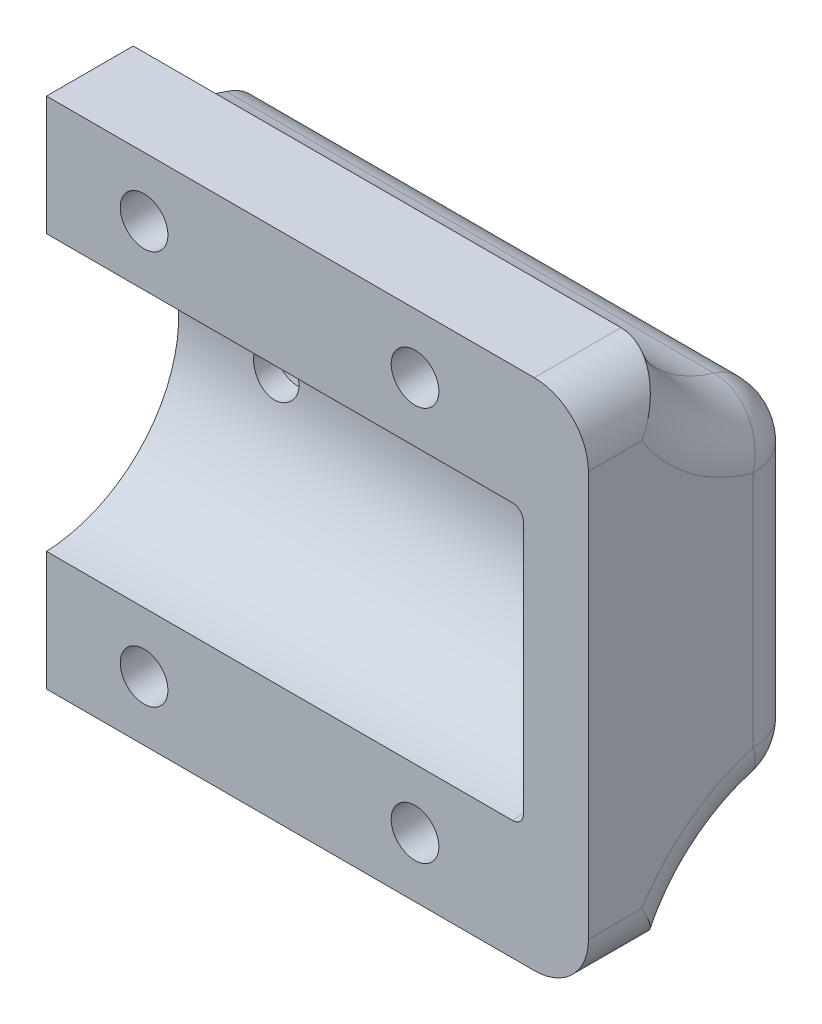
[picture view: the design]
ISO-10303-21;
HEADER;
FILE_DESCRIPTION(('STEP AP214'),'2;1');
FILE_NAME('part.step','',(''),(''),'','','');
FILE_SCHEMA(('AUTOMOTIVE_DESIGN { 1 0 10303 214 1 1 1 1 }'));
ENDSEC;
DATA;
#1=APPLICATION_CONTEXT('core data for automotive mechanical design processes');
#2=APPLICATION_PROTOCOL_DEFINITION('international standard','automotive_design',2000,#1);
#3=PRODUCT_CONTEXT('',#1,'mechanical');
#4=PRODUCT('Part','Part','',(#3));
#5=PRODUCT_RELATED_PRODUCT_CATEGORY('part','',(#4));
#6=PRODUCT_DEFINITION_FORMATION('','',#4);
#7=PRODUCT_DEFINITION_CONTEXT('part definition',#1,'design');
#8=PRODUCT_DEFINITION('design','',#6,#7);
#9=PRODUCT_DEFINITION_SHAPE('','',#8);
#10=(LENGTH_UNIT() NAMED_UNIT(*) SI_UNIT(.MILLI.,.METRE.));
#11=(NAMED_UNIT(*) PLANE_ANGLE_UNIT() SI_UNIT($,.RADIAN.));
#12=(NAMED_UNIT(*) SI_UNIT($,.STERADIAN.) SOLID_ANGLE_UNIT());
#13=UNCERTAINTY_MEASURE_WITH_UNIT(LENGTH_MEASURE(1.E-05),#10,'distance_accuracy_value','');
#14=(GEOMETRIC_REPRESENTATION_CONTEXT(3) GLOBAL_UNCERTAINTY_ASSIGNED_CONTEXT((#13)) GLOBAL_UNIT_ASSIGNED_CONTEXT((#10,
#11,#12)) REPRESENTATION_CONTEXT('',''));
#15=CARTESIAN_POINT('',(0.,0.,0.));
#16=DIRECTION('',(0.,0.,1.));
#17=DIRECTION('',(1.,0.,0.));
#18=AXIS2_PLACEMENT_3D('',#15,#16,#17);
#19=CARTESIAN_POINT('',(9.,18.1901536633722,-20.2));
#20=DIRECTION('',(0.,0.,1.));
#21=DIRECTION('',(1.,0.,0.));
#22=AXIS2_PLACEMENT_3D('',#19,#20,#21);
#23=CYLINDRICAL_SURFACE('',#22,2.1);
#24=CARTESIAN_POINT('',(11.1,18.1901536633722,-11.9525931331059));
#25=CARTESIAN_POINT('',(11.1000004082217,18.2649816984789,-11.8609818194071));
#26=CARTESIAN_POINT('',(11.0960052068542,18.3410787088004,-11.7703655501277));
#27=CARTESIAN_POINT('',(11.079154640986,18.4953429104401,-11.5916495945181));
#28=CARTESIAN_POINT('',(11.0662941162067,18.5735112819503,-11.5035514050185));
#29=CARTESIAN_POINT('',(11.0307187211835,18.7311800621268,-11.3305862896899));
#30=CARTESIAN_POINT('',(11.008006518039,18.8106801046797,-11.2457184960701));
#31=CARTESIAN_POINT('',(10.9516676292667,18.9699774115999,-11.0800757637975));
#32=CARTESIAN_POINT('',(10.9180497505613,19.0497743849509,-10.9992975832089));
#33=CARTESIAN_POINT('',(10.8308817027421,19.2241599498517,-10.8271837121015));
#34=CARTESIAN_POINT('',(10.7746996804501,19.3185407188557,-10.7369349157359));
#35=CARTESIAN_POINT('',(10.6433310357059,19.5024767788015,-10.5659415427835));
#36=CARTESIAN_POINT('',(10.5681775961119,19.5920401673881,-10.4851807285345));
#37=CARTESIAN_POINT('',(10.4124724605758,19.7473465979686,-10.3485749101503));
#38=CARTESIAN_POINT('',(10.3350536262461,19.8145413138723,-10.2908319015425));
#39=CARTESIAN_POINT('',(10.1666705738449,19.9393955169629,-10.185421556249));
#40=CARTESIAN_POINT('',(10.0757076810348,19.9970559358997,-10.1377532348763));
#41=CARTESIAN_POINT('',(9.88077297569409,20.0997260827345,-10.0540279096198));
#42=CARTESIAN_POINT('',(9.77669657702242,20.1446234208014,-10.0180736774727));
#43=CARTESIAN_POINT('',(9.55915324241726,20.217581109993,-9.96014901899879));
#44=CARTESIAN_POINT('',(9.44569603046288,20.2456586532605,-9.93816431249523));
#45=CARTESIAN_POINT('',(9.23105328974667,20.2798029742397,-9.91150655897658));
#46=CARTESIAN_POINT('',(9.13053901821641,20.2885138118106,-9.90475177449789));
#47=CARTESIAN_POINT('',(8.92919774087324,20.291368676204,-9.90253351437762));
#48=CARTESIAN_POINT('',(8.8283709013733,20.2855194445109,-9.90706481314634));
#49=CARTESIAN_POINT('',(8.63670917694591,20.2605900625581,-9.9264973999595));
#50=CARTESIAN_POINT('',(8.54566955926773,20.2424669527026,-9.94064885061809));
#51=CARTESIAN_POINT('',(8.36851717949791,20.1950573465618,-9.97800381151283));
#52=CARTESIAN_POINT('',(8.28240458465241,20.1657704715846,-10.0012076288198));
#53=CARTESIAN_POINT('',(8.11351382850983,20.0961520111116,-10.057031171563));
#54=CARTESIAN_POINT('',(8.03102032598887,20.0554141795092,-10.0900002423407));
#55=CARTESIAN_POINT('',(7.87469363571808,19.9654928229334,-10.1638885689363));
#56=CARTESIAN_POINT('',(7.80086354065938,19.916306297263,-10.2048106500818));
#57=CARTESIAN_POINT('',(7.65342350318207,19.8045812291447,-10.2993903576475));
#58=CARTESIAN_POINT('',(7.58112519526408,19.7411373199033,-10.3540156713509));
#59=CARTESIAN_POINT('',(7.44864950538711,19.6086416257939,-10.4705997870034));
#60=CARTESIAN_POINT('',(7.38848087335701,19.539585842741,-10.5325638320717));
#61=CARTESIAN_POINT('',(7.24928027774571,19.3582334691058,-10.6991263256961));
#62=CARTESIAN_POINT('',(7.1786764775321,19.2434643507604,-10.8081002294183));
#63=CARTESIAN_POINT('',(7.06304899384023,19.0117757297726,-11.0368323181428));
#64=CARTESIAN_POINT('',(7.01808035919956,18.8948521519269,-11.1566130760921));
#65=CARTESIAN_POINT('',(6.96003177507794,18.6960820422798,-11.3684940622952));
#66=CARTESIAN_POINT('',(6.94151292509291,18.6137519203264,-11.458733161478));
#67=CARTESIAN_POINT('',(6.9146193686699,18.4509240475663,-11.6423762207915));
#68=CARTESIAN_POINT('',(6.90624901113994,18.3704270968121,-11.7357815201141));
#69=CARTESIAN_POINT('',(6.89860747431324,18.211798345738,-11.9252394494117));
#70=CARTESIAN_POINT('',(6.89935534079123,18.1336718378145,-12.02129720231));
#71=CARTESIAN_POINT('',(6.90909288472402,17.9803767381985,-12.215348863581));
#72=CARTESIAN_POINT('',(6.91808479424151,17.9052089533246,-12.3133432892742));
#73=CARTESIAN_POINT('',(6.94847966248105,17.7297495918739,-12.548910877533));
#74=CARTESIAN_POINT('',(6.97333321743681,17.6309580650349,-12.6871627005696));
#75=CARTESIAN_POINT('',(7.03594105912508,17.4401097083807,-12.9654428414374));
#76=CARTESIAN_POINT('',(7.07370249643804,17.3480566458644,-13.1054721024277));
#77=CARTESIAN_POINT('',(7.16111607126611,17.1712270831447,-13.3858891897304));
#78=CARTESIAN_POINT('',(7.21073913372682,17.0864334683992,-13.5262753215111));
#79=CARTESIAN_POINT('',(7.32164906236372,16.9241337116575,-13.8065398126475));
#80=CARTESIAN_POINT('',(7.38292820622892,16.8466227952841,-13.9464184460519));
#81=CARTESIAN_POINT('',(7.50653107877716,16.7114833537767,-14.2008953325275));
#82=CARTESIAN_POINT('',(7.56695979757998,16.6526994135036,-14.3158028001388));
#83=CARTESIAN_POINT('',(7.69768262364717,16.5404745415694,-14.5431696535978));
#84=CARTESIAN_POINT('',(7.76800164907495,16.4870477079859,-14.6556220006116));
#85=CARTESIAN_POINT('',(7.88295871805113,16.4112939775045,-14.8208015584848));
#86=CARTESIAN_POINT('',(7.92311995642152,16.386643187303,-14.8755872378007));
#87=CARTESIAN_POINT('',(8.00703452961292,16.3391136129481,-14.9831227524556));
#88=CARTESIAN_POINT('',(8.0507860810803,16.316233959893,-15.0358735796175));
#89=CARTESIAN_POINT('',(8.14233999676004,16.2726083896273,-15.1382052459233));
#90=CARTESIAN_POINT('',(8.19012175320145,16.2518526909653,-15.1878001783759));
#91=CARTESIAN_POINT('',(8.29073639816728,16.2128182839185,-15.282583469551));
#92=CARTESIAN_POINT('',(8.34355978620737,16.1945350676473,-15.327779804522));
#93=CARTESIAN_POINT('',(8.44011950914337,16.1657201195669,-15.4000154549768));
#94=CARTESIAN_POINT('',(8.48242076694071,16.154432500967,-15.4286501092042));
#95=CARTESIAN_POINT('',(8.57060452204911,16.1340245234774,-15.4808751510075));
#96=CARTESIAN_POINT('',(8.61648761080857,16.1249045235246,-15.5044647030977));
#97=CARTESIAN_POINT('',(8.71244367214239,16.1093604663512,-15.5449251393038));
#98=CARTESIAN_POINT('',(8.76256654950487,16.1029761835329,-15.5616967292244));
#99=CARTESIAN_POINT('',(8.86533402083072,16.09384669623,-15.5857480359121));
#100=CARTESIAN_POINT('',(8.9179716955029,16.0910920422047,-15.5930523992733));
#101=CARTESIAN_POINT('',(9.01742427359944,16.0897076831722,-15.5967198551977));
#102=CARTESIAN_POINT('',(9.06419041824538,16.0906280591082,-15.5942763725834));
#103=CARTESIAN_POINT('',(9.15647273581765,16.0954799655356,-15.5814486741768));
#104=CARTESIAN_POINT('',(9.2019873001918,16.099415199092,-15.5710546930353));
#105=CARTESIAN_POINT('',(9.30132155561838,16.1111440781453,-15.5402783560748));
#106=CARTESIAN_POINT('',(9.35448350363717,16.1196412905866,-15.5180867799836));
#107=CARTESIAN_POINT('',(9.45643323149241,16.1396935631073,-15.466303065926));
#108=CARTESIAN_POINT('',(9.50521035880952,16.1512558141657,-15.4366935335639));
#109=CARTESIAN_POINT('',(9.59370830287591,16.1753614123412,-15.3757510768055));
#110=CARTESIAN_POINT('',(9.63384350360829,16.1876779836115,-15.3449169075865));
#111=CARTESIAN_POINT('',(9.71115189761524,16.2138120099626,-15.2802852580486));
#112=CARTESIAN_POINT('',(9.74832251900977,16.2276307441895,-15.2464852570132));
#113=CARTESIAN_POINT('',(9.85609061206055,16.2710027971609,-15.1417608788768));
#114=CARTESIAN_POINT('',(9.92279602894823,16.3024287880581,-15.0676226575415));
#115=CARTESIAN_POINT('',(10.0559206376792,16.3731851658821,-14.9052652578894));
#116=CARTESIAN_POINT('',(10.1212987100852,16.4130123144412,-14.8164349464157));
#117=CARTESIAN_POINT('',(10.2442408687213,16.4968163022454,-14.6352855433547));
#118=CARTESIAN_POINT('',(10.3017961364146,16.540797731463,-14.5429626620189));
#119=CARTESIAN_POINT('',(10.4103940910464,16.6326381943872,-14.3560848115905));
#120=CARTESIAN_POINT('',(10.4614192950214,16.6805070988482,-14.2615246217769));
#121=CARTESIAN_POINT('',(10.5574926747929,16.7798395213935,-14.0712530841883));
#122=CARTESIAN_POINT('',(10.6025395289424,16.8313038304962,-13.9755414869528));
#123=CARTESIAN_POINT('',(10.7074136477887,16.9634097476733,-13.7372076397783));
#124=CARTESIAN_POINT('',(10.7638752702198,17.0461410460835,-13.5942491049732));
#125=CARTESIAN_POINT('',(10.8646655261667,17.2190559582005,-13.3084330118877));
#126=CARTESIAN_POINT('',(10.9089860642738,17.3092444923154,-13.1655755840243));
#127=CARTESIAN_POINT('',(10.9846343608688,17.4963501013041,-12.8818015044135));
#128=CARTESIAN_POINT('',(11.0160208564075,17.5932343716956,-12.7408789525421));
#129=CARTESIAN_POINT('',(11.0648004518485,17.793645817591,-12.4614810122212));
#130=CARTESIAN_POINT('',(11.0822089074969,17.8971655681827,-12.3230031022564));
#131=CARTESIAN_POINT('',(11.0944283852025,18.0342349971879,-12.1471010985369));
#132=CARTESIAN_POINT('',(11.0965021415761,18.0650709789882,-12.1079938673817));
#133=CARTESIAN_POINT('',(11.0992886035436,18.1272469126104,-12.0300628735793));
#134=CARTESIAN_POINT('',(11.0999998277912,18.1585873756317,-11.9912394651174));
#135=CARTESIAN_POINT('',(11.1,18.1901536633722,-11.9525931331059));
#136=B_SPLINE_CURVE_WITH_KNOTS('',3,(#24,#25,#26,#27,#28,#29,#30,#31,#32,#33,#34,#35,#36,#37,
#38,#39,#40,#41,#42,#43,#44,#45,#46,#47,#48,#49,#50,#51,#52,#53,#54,#55,#56,#57,#58,#59,#60,#61,
#62,#63,#64,#65,#66,#67,#68,#69,#70,#71,#72,#73,#74,#75,#76,#77,#78,#79,#80,#81,#82,#83,#84,#85,
#86,#87,#88,#89,#90,#91,#92,#93,#94,#95,#96,#97,#98,#99,#100,#101,#102,#103,#104,#105,#106,#107,
#108,#109,#110,#111,#112,#113,#114,#115,#116,#117,#118,#119,#120,#121,#122,#123,#124,#125,#126,
#127,#128,#129,#130,#131,#132,#133,#134,#135),.UNSPECIFIED.,.T.,.F.,(4,2,2,2,2,2,2,2,2,2,2,2,2,
2,2,2,2,2,2,2,2,2,2,2,2,2,2,2,2,2,2,2,2,2,2,2,2,2,2,2,2,2,2,2,2,2,2,2,2,2,2,2,2,2,2,4),(0.,
0.354821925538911,0.709850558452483,1.06478313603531,1.41942979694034,1.84446916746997,
2.26877019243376,2.62034948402,2.97189439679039,3.32644530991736,3.6806332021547,
3.98236309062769,4.2839533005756,4.56438465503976,4.84482552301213,5.13685035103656,
5.42897911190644,5.75961189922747,6.09048234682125,6.60747457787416,7.12557285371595,
7.49574693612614,7.86607959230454,8.23718591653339,8.60839274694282,9.12286436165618,
9.63762144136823,10.15112946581,10.6642984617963,11.0914931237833,11.5197840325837,
11.7364714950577,11.9530519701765,12.168585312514,12.3837202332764,12.5403530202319,
12.6970117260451,12.8558765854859,13.014327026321,13.1540104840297,13.2938657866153,
13.4675871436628,13.6417197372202,13.7977587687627,13.9539317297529,14.2668418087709,
14.618178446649,14.9699079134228,15.3225601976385,15.675290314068,16.1983356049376,
16.7217288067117,17.2427182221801,17.7631345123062,17.9126540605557,18.062336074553),.UNSPECIFIED.);
#137=CARTESIAN_POINT('',(11.1,18.1901536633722,-11.9525931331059));
#138=VERTEX_POINT('',#137);
#139=EDGE_CURVE('E307',#138,#138,#136,.T.);
#140=ORIENTED_EDGE('',*,*,#139,.F.);
#141=EDGE_LOOP('',(#140));
#142=FACE_BOUND('',#141,.T.);
#143=CARTESIAN_POINT('',(9.,18.1901536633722,-5.));
#144=DIRECTION('',(0.,0.,1.));
#145=DIRECTION('',(1.,0.,0.));
#146=AXIS2_PLACEMENT_3D('',#143,#144,#145);
#147=CIRCLE('',#146,2.1);
#148=CARTESIAN_POINT('',(11.1,18.1901536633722,-5.));
#149=VERTEX_POINT('',#148);
#150=EDGE_CURVE('E445',#149,#149,#147,.F.);
#151=ORIENTED_EDGE('',*,*,#150,.F.);
#152=EDGE_LOOP('',(#151));
#153=FACE_BOUND('',#152,.T.);
#154=ADVANCED_FACE('F44',(#142,#153),#23,.F.);
#155=CARTESIAN_POINT('',(34.,-18.1901536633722,-20.2));
#156=DIRECTION('',(0.,0.,1.));
#157=DIRECTION('',(1.,0.,0.));
#158=AXIS2_PLACEMENT_3D('',#155,#156,#157);
#159=CYLINDRICAL_SURFACE('',#158,2.1);
#160=CARTESIAN_POINT('',(36.1,-18.1901536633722,-11.9525931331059));
#161=CARTESIAN_POINT('',(36.100002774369,-18.0940217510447,-12.0702912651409));
#162=CARTESIAN_POINT('',(36.0934104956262,-17.9999131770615,-12.1897181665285));
#163=CARTESIAN_POINT('',(36.0685563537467,-17.8164509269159,-12.4310664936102));
#164=CARTESIAN_POINT('',(36.0502835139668,-17.7271018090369,-12.5529901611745));
#165=CARTESIAN_POINT('',(36.0030754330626,-17.5530775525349,-12.799241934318));
#166=CARTESIAN_POINT('',(35.9740755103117,-17.4684344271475,-12.9235801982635));
#167=CARTESIAN_POINT('',(35.9062633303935,-17.3047106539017,-13.1731361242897));
#168=CARTESIAN_POINT('',(35.8674552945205,-17.2256276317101,-13.2983533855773));
#169=CARTESIAN_POINT('',(35.7780373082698,-17.0689165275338,-13.5559370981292));
#170=CARTESIAN_POINT('',(35.7268925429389,-16.9916118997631,-13.6883152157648));
#171=CARTESIAN_POINT('',(35.614024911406,-16.8434507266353,-13.9523654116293));
#172=CARTESIAN_POINT('',(35.5522914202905,-16.7726007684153,-14.084036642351));
#173=CARTESIAN_POINT('',(35.4177380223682,-16.6380390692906,-14.3444353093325));
#174=CARTESIAN_POINT('',(35.3449763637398,-16.574292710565,-14.4731743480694));
#175=CARTESIAN_POINT('',(35.2257392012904,-16.4842757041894,-14.6623940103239));
#176=CARTESIAN_POINT('',(35.184346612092,-16.4552239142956,-14.7247727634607));
#177=CARTESIAN_POINT('',(35.0976680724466,-16.399121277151,-14.8476833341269));
#178=CARTESIAN_POINT('',(35.0523841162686,-16.3720694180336,-14.9082160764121));
#179=CARTESIAN_POINT('',(34.9748896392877,-16.3298454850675,-15.0045736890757));
#180=CARTESIAN_POINT('',(34.9440728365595,-16.3139938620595,-15.0412225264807));
#181=CARTESIAN_POINT('',(34.8803646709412,-16.283268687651,-15.1131282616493));
#182=CARTESIAN_POINT('',(34.847472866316,-16.2683953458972,-15.1483848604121));
#183=CARTESIAN_POINT('',(34.7794212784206,-16.2398046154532,-15.2169564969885));
#184=CARTESIAN_POINT('',(34.7442675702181,-16.2260843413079,-15.2502763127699));
#185=CARTESIAN_POINT('',(34.6713037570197,-16.199964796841,-15.3144084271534));
#186=CARTESIAN_POINT('',(34.6334954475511,-16.1875646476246,-15.3452223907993));
#187=CARTESIAN_POINT('',(34.5509635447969,-16.1632174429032,-15.4063298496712));
#188=CARTESIAN_POINT('',(34.5059256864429,-16.151435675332,-15.4362723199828));
#189=CARTESIAN_POINT('',(34.4118604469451,-16.1303757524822,-15.4902768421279));
#190=CARTESIAN_POINT('',(34.3628373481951,-16.1210949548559,-15.5143450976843));
#191=CARTESIAN_POINT('',(34.2702128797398,-16.1071844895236,-15.5506399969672));
#192=CARTESIAN_POINT('',(34.2272345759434,-16.1020171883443,-15.5642210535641));
#193=CARTESIAN_POINT('',(34.1394620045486,-16.0943286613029,-15.5844806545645));
#194=CARTESIAN_POINT('',(34.0946705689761,-16.0918034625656,-15.59116956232));
#195=CARTESIAN_POINT('',(34.0043045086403,-16.0896702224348,-15.5968178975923));
#196=CARTESIAN_POINT('',(33.9587272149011,-16.090075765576,-15.5957413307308));
#197=CARTESIAN_POINT('',(33.868520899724,-16.0937858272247,-15.5859254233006));
#198=CARTESIAN_POINT('',(33.8238928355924,-16.097093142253,-15.5771786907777));
#199=CARTESIAN_POINT('',(33.726945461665,-16.1072888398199,-15.5503739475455));
#200=CARTESIAN_POINT('',(33.6751610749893,-16.1148165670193,-15.5306610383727));
#201=CARTESIAN_POINT('',(33.5755980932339,-16.1328598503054,-15.4838919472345));
#202=CARTESIAN_POINT('',(33.5278292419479,-16.1433824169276,-15.4568185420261));
#203=CARTESIAN_POINT('',(33.4024008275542,-16.1752954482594,-15.3757041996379));
#204=CARTESIAN_POINT('',(33.3287147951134,-16.1989735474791,-15.3165116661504));
#205=CARTESIAN_POINT('',(33.1907907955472,-16.2509220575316,-15.189824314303));
#206=CARTESIAN_POINT('',(33.1265834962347,-16.2792067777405,-15.1223037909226));
#207=CARTESIAN_POINT('',(32.9987070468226,-16.342707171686,-14.974543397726));
#208=CARTESIAN_POINT('',(32.9359212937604,-16.3783449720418,-14.8937288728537));
#209=CARTESIAN_POINT('',(32.8175149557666,-16.4533074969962,-14.7285800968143));
#210=CARTESIAN_POINT('',(32.7619024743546,-16.4926363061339,-14.6442420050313));
#211=CARTESIAN_POINT('',(32.6565918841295,-16.5746922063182,-14.4732710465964));
#212=CARTESIAN_POINT('',(32.606907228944,-16.6174266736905,-14.3866334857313));
#213=CARTESIAN_POINT('',(32.5128745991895,-16.7060287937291,-14.212063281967));
#214=CARTESIAN_POINT('',(32.468528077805,-16.7518972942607,-14.1241302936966));
#215=CARTESIAN_POINT('',(32.3587641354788,-16.8760511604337,-13.8927485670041));
#216=CARTESIAN_POINT('',(32.297343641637,-16.9567929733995,-13.748703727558));
#217=CARTESIAN_POINT('',(32.1868139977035,-17.1259390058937,-13.4602836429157));
#218=CARTESIAN_POINT('',(32.1377128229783,-17.214348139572,-13.3159082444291));
#219=CARTESIAN_POINT('',(32.0523311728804,-17.3984085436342,-13.0283206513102));
#220=CARTESIAN_POINT('',(32.0160297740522,-17.4940476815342,-12.8851069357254));
#221=CARTESIAN_POINT('',(31.9572461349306,-17.6923194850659,-12.600768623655));
#222=CARTESIAN_POINT('',(31.9347547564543,-17.7949474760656,-12.4596427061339));
#223=CARTESIAN_POINT('',(31.9104341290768,-17.9697843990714,-12.2291816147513));
#224=CARTESIAN_POINT('',(31.9041388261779,-18.0401551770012,-12.138908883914));
#225=CARTESIAN_POINT('',(31.8987878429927,-18.1833865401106,-11.960089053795));
#226=CARTESIAN_POINT('',(31.8997334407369,-18.256247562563,-11.8715422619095));
#227=CARTESIAN_POINT('',(31.9096034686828,-18.4039577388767,-11.6967795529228));
#228=CARTESIAN_POINT('',(31.918515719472,-18.4788036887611,-11.6105602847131));
#229=CARTESIAN_POINT('',(31.945151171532,-18.630028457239,-11.4408760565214));
#230=CARTESIAN_POINT('',(31.9628737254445,-18.7064071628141,-11.3574108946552));
#231=CARTESIAN_POINT('',(32.0185967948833,-18.8957075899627,-11.1558189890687));
#232=CARTESIAN_POINT('',(32.0621933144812,-19.0091176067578,-11.0396084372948));
#233=CARTESIAN_POINT('',(32.1735260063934,-19.2340346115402,-10.817266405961));
#234=CARTESIAN_POINT('',(32.2412305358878,-19.345543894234,-10.7111219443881));
#235=CARTESIAN_POINT('',(32.3843524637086,-19.5356281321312,-10.5359771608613));
#236=CARTESIAN_POINT('',(32.4541763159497,-19.6157637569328,-10.4641234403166));
#237=CARTESIAN_POINT('',(32.610166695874,-19.768194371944,-10.3304693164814));
#238=CARTESIAN_POINT('',(32.6963132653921,-19.8404987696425,-10.2686568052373));
#239=CARTESIAN_POINT('',(32.8685503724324,-19.9618675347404,-10.1668048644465));
#240=CARTESIAN_POINT('',(32.9521889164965,-20.0127943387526,-10.1248511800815));
#241=CARTESIAN_POINT('',(33.129289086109,-20.1037240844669,-10.0508526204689));
#242=CARTESIAN_POINT('',(33.2227474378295,-20.1437306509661,-10.0188044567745));
#243=CARTESIAN_POINT('',(33.4179258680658,-20.2105207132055,-9.96573471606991));
#244=CARTESIAN_POINT('',(33.5196901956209,-20.2372271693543,-9.94477733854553));
#245=CARTESIAN_POINT('',(33.7278054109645,-20.2751180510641,-9.91514433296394));
#246=CARTESIAN_POINT('',(33.8341541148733,-20.2863097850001,-9.90646292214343));
#247=CARTESIAN_POINT('',(34.0366479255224,-20.2920236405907,-9.90202559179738));
#248=CARTESIAN_POINT('',(34.1327262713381,-20.2881309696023,-9.90504055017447));
#249=CARTESIAN_POINT('',(34.3225911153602,-20.2674231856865,-9.92116439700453));
#250=CARTESIAN_POINT('',(34.4163780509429,-20.2506105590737,-9.93427134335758));
#251=CARTESIAN_POINT('',(34.5974377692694,-20.2055009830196,-9.96974995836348));
#252=CARTESIAN_POINT('',(34.6847967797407,-20.1774137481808,-9.99195258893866));
#253=CARTESIAN_POINT('',(34.852892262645,-20.1112835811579,-10.0448432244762));
#254=CARTESIAN_POINT('',(34.9336274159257,-20.073238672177,-10.0755329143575));
#255=CARTESIAN_POINT('',(35.0935007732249,-19.9854926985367,-10.1473346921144));
#256=CARTESIAN_POINT('',(35.1719581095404,-19.9350890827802,-10.1890976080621));
#257=CARTESIAN_POINT('',(35.3187149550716,-19.8270147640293,-10.2802635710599));
#258=CARTESIAN_POINT('',(35.3870091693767,-19.7693403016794,-10.3296705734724));
#259=CARTESIAN_POINT('',(35.5423015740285,-19.6210739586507,-10.4592301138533));
#260=CARTESIAN_POINT('',(35.6234437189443,-19.5275480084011,-10.5430681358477));
#261=CARTESIAN_POINT('',(35.7646603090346,-19.3348454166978,-10.7214260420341));
#262=CARTESIAN_POINT('',(35.8246818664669,-19.2356553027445,-10.8159719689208));
#263=CARTESIAN_POINT('',(35.9451724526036,-18.9967063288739,-11.0514988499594));
#264=CARTESIAN_POINT('',(35.996724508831,-18.8561825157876,-11.1962312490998));
#265=CARTESIAN_POINT('',(36.068685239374,-18.5788492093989,-11.4959765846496));
#266=CARTESIAN_POINT('',(36.089108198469,-18.4420380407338,-11.6509847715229));
#267=CARTESIAN_POINT('',(36.0988988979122,-18.2689700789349,-11.8567958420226));
#268=CARTESIAN_POINT('',(36.0999988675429,-18.2293933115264,-11.9045504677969));
#269=CARTESIAN_POINT('',(36.1,-18.1901536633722,-11.9525931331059));
#270=B_SPLINE_CURVE_WITH_KNOTS('',3,(#160,#161,#162,#163,#164,#165,#166,#167,#168,#169,#170,
#171,#172,#173,#174,#175,#176,#177,#178,#179,#180,#181,#182,#183,#184,#185,#186,#187,#188,#189,
#190,#191,#192,#193,#194,#195,#196,#197,#198,#199,#200,#201,#202,#203,#204,#205,#206,#207,#208,
#209,#210,#211,#212,#213,#214,#215,#216,#217,#218,#219,#220,#221,#222,#223,#224,#225,#226,#227,
#228,#229,#230,#231,#232,#233,#234,#235,#236,#237,#238,#239,#240,#241,#242,#243,#244,#245,#246,
#247,#248,#249,#250,#251,#252,#253,#254,#255,#256,#257,#258,#259,#260,#261,#262,#263,#264,#265,
#266,#267,#268,#269),.UNSPECIFIED.,.T.,.F.,(4,2,2,2,2,2,2,2,2,2,2,2,2,2,2,2,2,2,2,2,2,2,2,2,2,2,
2,2,2,2,2,2,2,2,2,2,2,2,2,2,2,2,2,2,2,2,2,2,2,2,2,2,2,2,4),(0.,0.455877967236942,
0.912184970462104,1.37128947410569,1.83019672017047,2.31453335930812,2.79935886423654,
3.28170754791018,3.52251308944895,3.76319594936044,3.9144562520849,4.06574886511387,
4.21665084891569,4.36745173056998,4.53312465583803,4.6986218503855,4.8341861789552,
4.96954636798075,5.10553437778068,5.24165358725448,5.40846713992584,5.57567443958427,
5.86634597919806,6.1579382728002,6.48253321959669,6.8074917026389,7.13317421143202,
7.45894518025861,7.98682932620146,8.51505434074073,9.04241183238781,9.56941999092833,
9.91308938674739,10.2568194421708,10.6000249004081,10.9432051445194,11.4458568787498,
11.9478512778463,12.3313441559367,12.7143711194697,13.0326529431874,13.3508289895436,
13.6708272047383,13.9906746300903,14.2778676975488,14.5650055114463,14.8470330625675,
15.1291166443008,15.4344648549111,15.7399715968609,16.1860724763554,16.6332826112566,
17.2545398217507,17.8755118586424,18.0615946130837),.UNSPECIFIED.);
#271=CARTESIAN_POINT('',(36.1,-18.1901536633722,-11.9525931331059));
#272=VERTEX_POINT('',#271);
#273=EDGE_CURVE('E362',#272,#272,#270,.T.);
#274=ORIENTED_EDGE('',*,*,#273,.F.);
#275=EDGE_LOOP('',(#274));
#276=FACE_BOUND('',#275,.T.);
#277=CARTESIAN_POINT('',(34.,-18.1901536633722,-5.));
#278=DIRECTION('',(0.,0.,1.));
#279=DIRECTION('',(1.,0.,0.));
#280=AXIS2_PLACEMENT_3D('',#277,#278,#279);
#281=CIRCLE('',#280,2.1);
#282=CARTESIAN_POINT('',(36.1,-18.1901536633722,-5.));
#283=VERTEX_POINT('',#282);
#284=EDGE_CURVE('E438',#283,#283,#281,.F.);
#285=ORIENTED_EDGE('',*,*,#284,.F.);
#286=EDGE_LOOP('',(#285));
#287=FACE_BOUND('',#286,.T.);
#288=ADVANCED_FACE('F336',(#276,#287),#159,.F.);
#289=CARTESIAN_POINT('',(9.,-18.1901536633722,-20.2));
#290=DIRECTION('',(0.,0.,1.));
#291=DIRECTION('',(1.,0.,0.));
#292=AXIS2_PLACEMENT_3D('',#289,#290,#291);
#293=CYLINDRICAL_SURFACE('',#292,2.1);
#294=CARTESIAN_POINT('',(11.1,-18.1901536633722,-11.9525931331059));
#295=CARTESIAN_POINT('',(11.100002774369,-18.0940217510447,-12.0702912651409));
#296=CARTESIAN_POINT('',(11.0934104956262,-17.9999131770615,-12.1897181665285));
#297=CARTESIAN_POINT('',(11.0685563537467,-17.8164509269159,-12.4310664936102));
#298=CARTESIAN_POINT('',(11.0502835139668,-17.7271018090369,-12.5529901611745));
#299=CARTESIAN_POINT('',(11.0030754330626,-17.5530775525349,-12.799241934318));
#300=CARTESIAN_POINT('',(10.9740755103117,-17.4684344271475,-12.9235801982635));
#301=CARTESIAN_POINT('',(10.9062633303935,-17.3047106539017,-13.1731361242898));
#302=CARTESIAN_POINT('',(10.8674552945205,-17.2256276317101,-13.2983533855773));
#303=CARTESIAN_POINT('',(10.7780373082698,-17.0689165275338,-13.5559370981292));
#304=CARTESIAN_POINT('',(10.7268925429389,-16.9916118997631,-13.6883152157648));
#305=CARTESIAN_POINT('',(10.614024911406,-16.8434507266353,-13.9523654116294));
#306=CARTESIAN_POINT('',(10.5522914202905,-16.7726007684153,-14.084036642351));
#307=CARTESIAN_POINT('',(10.4177380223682,-16.6380390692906,-14.3444353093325));
#308=CARTESIAN_POINT('',(10.3449763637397,-16.574292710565,-14.4731743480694));
#309=CARTESIAN_POINT('',(10.2257392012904,-16.4842757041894,-14.662394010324));
#310=CARTESIAN_POINT('',(10.184346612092,-16.4552239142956,-14.7247727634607));
#311=CARTESIAN_POINT('',(10.0976680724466,-16.399121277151,-14.847683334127));
#312=CARTESIAN_POINT('',(10.0523841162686,-16.3720694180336,-14.9082160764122));
#313=CARTESIAN_POINT('',(9.97488963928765,-16.3298454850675,-15.0045736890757));
#314=CARTESIAN_POINT('',(9.94407283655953,-16.3139938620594,-15.0412225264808));
#315=CARTESIAN_POINT('',(9.88036467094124,-16.283268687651,-15.1131282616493));
#316=CARTESIAN_POINT('',(9.84747286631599,-16.2683953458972,-15.1483848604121));
#317=CARTESIAN_POINT('',(9.77942127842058,-16.2398046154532,-15.2169564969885));
#318=CARTESIAN_POINT('',(9.74426757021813,-16.2260843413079,-15.2502763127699));
#319=CARTESIAN_POINT('',(9.67130375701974,-16.199964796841,-15.3144084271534));
#320=CARTESIAN_POINT('',(9.63349544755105,-16.1875646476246,-15.3452223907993));
#321=CARTESIAN_POINT('',(9.55096354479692,-16.1632174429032,-15.4063298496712));
#322=CARTESIAN_POINT('',(9.50592568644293,-16.151435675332,-15.4362723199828));
#323=CARTESIAN_POINT('',(9.41186044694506,-16.1303757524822,-15.4902768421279));
#324=CARTESIAN_POINT('',(9.36283734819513,-16.1210949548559,-15.5143450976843));
#325=CARTESIAN_POINT('',(9.27021287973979,-16.1071844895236,-15.5506399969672));
#326=CARTESIAN_POINT('',(9.22723457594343,-16.1020171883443,-15.5642210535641));
#327=CARTESIAN_POINT('',(9.1394620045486,-16.0943286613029,-15.5844806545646));
#328=CARTESIAN_POINT('',(9.09467056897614,-16.0918034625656,-15.59116956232));
#329=CARTESIAN_POINT('',(9.00430450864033,-16.0896702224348,-15.5968178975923));
#330=CARTESIAN_POINT('',(8.95872721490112,-16.090075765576,-15.5957413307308));
#331=CARTESIAN_POINT('',(8.86852089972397,-16.0937858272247,-15.5859254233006));
#332=CARTESIAN_POINT('',(8.8238928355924,-16.097093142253,-15.5771786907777));
#333=CARTESIAN_POINT('',(8.72694546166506,-16.1072888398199,-15.5503739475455));
#334=CARTESIAN_POINT('',(8.67516107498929,-16.1148165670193,-15.5306610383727));
#335=CARTESIAN_POINT('',(8.57559809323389,-16.1328598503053,-15.4838919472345));
#336=CARTESIAN_POINT('',(8.52782924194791,-16.1433824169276,-15.4568185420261));
#337=CARTESIAN_POINT('',(8.40240082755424,-16.1752954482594,-15.3757041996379));
#338=CARTESIAN_POINT('',(8.32871479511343,-16.1989735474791,-15.3165116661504));
#339=CARTESIAN_POINT('',(8.19079079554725,-16.2509220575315,-15.189824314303));
#340=CARTESIAN_POINT('',(8.12658349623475,-16.2792067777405,-15.1223037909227));
#341=CARTESIAN_POINT('',(7.99870704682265,-16.342707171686,-14.974543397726));
#342=CARTESIAN_POINT('',(7.93592129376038,-16.3783449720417,-14.8937288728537));
#343=CARTESIAN_POINT('',(7.81751495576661,-16.4533074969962,-14.7285800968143));
#344=CARTESIAN_POINT('',(7.76190247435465,-16.4926363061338,-14.6442420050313));
#345=CARTESIAN_POINT('',(7.65659188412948,-16.5746922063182,-14.4732710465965));
#346=CARTESIAN_POINT('',(7.60690722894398,-16.6174266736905,-14.3866334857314));
#347=CARTESIAN_POINT('',(7.51287459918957,-16.7060287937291,-14.212063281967));
#348=CARTESIAN_POINT('',(7.468528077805,-16.7518972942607,-14.1241302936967));
#349=CARTESIAN_POINT('',(7.3587641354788,-16.8760511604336,-13.8927485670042));
#350=CARTESIAN_POINT('',(7.29734364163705,-16.9567929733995,-13.748703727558));
#351=CARTESIAN_POINT('',(7.18681399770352,-17.1259390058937,-13.4602836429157));
#352=CARTESIAN_POINT('',(7.13771282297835,-17.214348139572,-13.3159082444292));
#353=CARTESIAN_POINT('',(7.05233117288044,-17.3984085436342,-13.0283206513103));
#354=CARTESIAN_POINT('',(7.01602977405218,-17.4940476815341,-12.8851069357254));
#355=CARTESIAN_POINT('',(6.95724613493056,-17.6923194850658,-12.6007686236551));
#356=CARTESIAN_POINT('',(6.93475475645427,-17.7949474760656,-12.459642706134));
#357=CARTESIAN_POINT('',(6.91043412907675,-17.9697843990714,-12.2291816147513));
#358=CARTESIAN_POINT('',(6.90413882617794,-18.0401551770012,-12.1389088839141));
#359=CARTESIAN_POINT('',(6.89878784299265,-18.1833865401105,-11.9600890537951));
#360=CARTESIAN_POINT('',(6.89973344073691,-18.2562475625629,-11.8715422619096));
#361=CARTESIAN_POINT('',(6.90960346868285,-18.4039577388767,-11.6967795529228));
#362=CARTESIAN_POINT('',(6.91851571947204,-18.478803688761,-11.6105602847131));
#363=CARTESIAN_POINT('',(6.94515117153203,-18.630028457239,-11.4408760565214));
#364=CARTESIAN_POINT('',(6.96287372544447,-18.706407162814,-11.3574108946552));
#365=CARTESIAN_POINT('',(7.01859679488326,-18.8957075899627,-11.1558189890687));
#366=CARTESIAN_POINT('',(7.06219331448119,-19.0091176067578,-11.0396084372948));
#367=CARTESIAN_POINT('',(7.17352600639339,-19.2340346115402,-10.817266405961));
#368=CARTESIAN_POINT('',(7.24123053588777,-19.345543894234,-10.7111219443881));
#369=CARTESIAN_POINT('',(7.38435246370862,-19.5356281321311,-10.5359771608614));
#370=CARTESIAN_POINT('',(7.45417631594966,-19.6157637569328,-10.4641234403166));
#371=CARTESIAN_POINT('',(7.610166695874,-19.768194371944,-10.3304693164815));
#372=CARTESIAN_POINT('',(7.69631326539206,-19.8404987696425,-10.2686568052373));
#373=CARTESIAN_POINT('',(7.86855037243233,-19.9618675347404,-10.1668048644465));
#374=CARTESIAN_POINT('',(7.9521889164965,-20.0127943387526,-10.1248511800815));
#375=CARTESIAN_POINT('',(8.12928908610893,-20.1037240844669,-10.0508526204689));
#376=CARTESIAN_POINT('',(8.22274743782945,-20.1437306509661,-10.0188044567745));
#377=CARTESIAN_POINT('',(8.41792586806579,-20.2105207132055,-9.96573471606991));
#378=CARTESIAN_POINT('',(8.5196901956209,-20.2372271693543,-9.94477733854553));
#379=CARTESIAN_POINT('',(8.72780541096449,-20.2751180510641,-9.91514433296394));
#380=CARTESIAN_POINT('',(8.8341541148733,-20.2863097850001,-9.90646292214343));
#381=CARTESIAN_POINT('',(9.03664792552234,-20.2920236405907,-9.90202559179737));
#382=CARTESIAN_POINT('',(9.13272627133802,-20.2881309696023,-9.90504055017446));
#383=CARTESIAN_POINT('',(9.3225911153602,-20.2674231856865,-9.92116439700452));
#384=CARTESIAN_POINT('',(9.41637805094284,-20.2506105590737,-9.93427134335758));
#385=CARTESIAN_POINT('',(9.59743776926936,-20.2055009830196,-9.96974995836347));
#386=CARTESIAN_POINT('',(9.68479677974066,-20.1774137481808,-9.99195258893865));
#387=CARTESIAN_POINT('',(9.85289226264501,-20.1112835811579,-10.0448432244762));
#388=CARTESIAN_POINT('',(9.93362741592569,-20.073238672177,-10.0755329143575));
#389=CARTESIAN_POINT('',(10.0935007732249,-19.9854926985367,-10.1473346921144));
#390=CARTESIAN_POINT('',(10.1719581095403,-19.9350890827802,-10.1890976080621));
#391=CARTESIAN_POINT('',(10.3187149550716,-19.8270147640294,-10.2802635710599));
#392=CARTESIAN_POINT('',(10.3870091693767,-19.7693403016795,-10.3296705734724));
#393=CARTESIAN_POINT('',(10.5423015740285,-19.6210739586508,-10.4592301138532));
#394=CARTESIAN_POINT('',(10.6234437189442,-19.5275480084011,-10.5430681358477));
#395=CARTESIAN_POINT('',(10.7646603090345,-19.3348454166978,-10.721426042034));
#396=CARTESIAN_POINT('',(10.8246818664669,-19.2356553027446,-10.8159719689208));
#397=CARTESIAN_POINT('',(10.9451724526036,-18.9967063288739,-11.0514988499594));
#398=CARTESIAN_POINT('',(10.9967245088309,-18.8561825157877,-11.1962312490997));
#399=CARTESIAN_POINT('',(11.068685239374,-18.5788492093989,-11.4959765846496));
#400=CARTESIAN_POINT('',(11.089108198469,-18.4420380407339,-11.6509847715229));
#401=CARTESIAN_POINT('',(11.0988988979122,-18.268970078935,-11.8567958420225));
#402=CARTESIAN_POINT('',(11.0999988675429,-18.2293933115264,-11.9045504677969));
#403=CARTESIAN_POINT('',(11.1,-18.1901536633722,-11.9525931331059));
#404=B_SPLINE_CURVE_WITH_KNOTS('',3,(#294,#295,#296,#297,#298,#299,#300,#301,#302,#303,#304,
#305,#306,#307,#308,#309,#310,#311,#312,#313,#314,#315,#316,#317,#318,#319,#320,#321,#322,#323,
#324,#325,#326,#327,#328,#329,#330,#331,#332,#333,#334,#335,#336,#337,#338,#339,#340,#341,#342,
#343,#344,#345,#346,#347,#348,#349,#350,#351,#352,#353,#354,#355,#356,#357,#358,#359,#360,#361,
#362,#363,#364,#365,#366,#367,#368,#369,#370,#371,#372,#373,#374,#375,#376,#377,#378,#379,#380,
#381,#382,#383,#384,#385,#386,#387,#388,#389,#390,#391,#392,#393,#394,#395,#396,#397,#398,#399,
#400,#401,#402,#403),.UNSPECIFIED.,.T.,.F.,(4,2,2,2,2,2,2,2,2,2,2,2,2,2,2,2,2,2,2,2,2,2,2,2,2,2,
2,2,2,2,2,2,2,2,2,2,2,2,2,2,2,2,2,2,2,2,2,2,2,2,2,2,2,2,4),(0.,0.455877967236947,
0.91218497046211,1.37128947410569,1.83019672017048,2.31453335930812,2.79935886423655,
3.28170754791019,3.52251308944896,3.76319594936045,3.91445625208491,4.06574886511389,
4.21665084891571,4.36745173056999,4.53312465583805,4.69862185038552,4.83418617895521,
4.96954636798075,5.10553437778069,5.24165358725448,5.40846713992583,5.57567443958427,
5.86634597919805,6.15793827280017,6.48253321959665,6.80749170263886,7.13317421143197,
7.45894518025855,7.98682932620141,8.51505434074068,9.04241183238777,9.56941999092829,
9.91308938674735,10.2568194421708,10.6000249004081,10.9432051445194,11.4458568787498,
11.9478512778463,12.3313441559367,12.7143711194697,13.0326529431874,13.3508289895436,
13.6708272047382,13.9906746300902,14.2778676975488,14.5650055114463,14.8470330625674,
15.1291166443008,15.4344648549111,15.7399715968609,16.1860724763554,16.6332826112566,
17.2545398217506,17.8755118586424,18.0615946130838),.UNSPECIFIED.);
#405=CARTESIAN_POINT('',(11.1,-18.1901536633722,-11.9525931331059));
#406=VERTEX_POINT('',#405);
#407=EDGE_CURVE('E386',#406,#406,#404,.T.);
#408=ORIENTED_EDGE('',*,*,#407,.F.);
#409=EDGE_LOOP('',(#408));
#410=FACE_BOUND('',#409,.T.);
#411=CARTESIAN_POINT('',(9.,-18.1901536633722,-5.));
#412=DIRECTION('',(0.,0.,1.));
#413=DIRECTION('',(1.,0.,0.));
#414=AXIS2_PLACEMENT_3D('',#411,#412,#413);
#415=CIRCLE('',#414,2.1);
#416=CARTESIAN_POINT('',(11.1,-18.1901536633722,-5.));
#417=VERTEX_POINT('',#416);
#418=EDGE_CURVE('E433',#417,#417,#415,.F.);
#419=ORIENTED_EDGE('',*,*,#418,.F.);
#420=EDGE_LOOP('',(#419));
#421=FACE_BOUND('',#420,.T.);
#422=ADVANCED_FACE('F342',(#410,#421),#293,.F.);
#423=CARTESIAN_POINT('',(34.,18.1901536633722,-20.2));
#424=DIRECTION('',(0.,0.,1.));
#425=DIRECTION('',(1.,0.,0.));
#426=AXIS2_PLACEMENT_3D('',#423,#424,#425);
#427=CYLINDRICAL_SURFACE('',#426,2.1);
#428=CARTESIAN_POINT('',(36.1,18.1901536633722,-11.9525931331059));
#429=CARTESIAN_POINT('',(36.1000004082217,18.2649816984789,-11.8609818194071));
#430=CARTESIAN_POINT('',(36.0960052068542,18.3410787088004,-11.7703655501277));
#431=CARTESIAN_POINT('',(36.079154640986,18.4953429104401,-11.5916495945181));
#432=CARTESIAN_POINT('',(36.0662941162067,18.5735112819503,-11.5035514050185));
#433=CARTESIAN_POINT('',(36.0307187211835,18.7311800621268,-11.3305862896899));
#434=CARTESIAN_POINT('',(36.008006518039,18.8106801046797,-11.2457184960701));
#435=CARTESIAN_POINT('',(35.9516676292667,18.9699774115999,-11.0800757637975));
#436=CARTESIAN_POINT('',(35.9180497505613,19.0497743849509,-10.9992975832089));
#437=CARTESIAN_POINT('',(35.8308817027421,19.2241599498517,-10.8271837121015));
#438=CARTESIAN_POINT('',(35.7746996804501,19.3185407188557,-10.7369349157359));
#439=CARTESIAN_POINT('',(35.6433310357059,19.5024767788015,-10.5659415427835));
#440=CARTESIAN_POINT('',(35.5681775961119,19.5920401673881,-10.4851807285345));
#441=CARTESIAN_POINT('',(35.4124724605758,19.7473465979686,-10.3485749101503));
#442=CARTESIAN_POINT('',(35.3350536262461,19.8145413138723,-10.2908319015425));
#443=CARTESIAN_POINT('',(35.1666705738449,19.9393955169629,-10.185421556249));
#444=CARTESIAN_POINT('',(35.0757076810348,19.9970559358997,-10.1377532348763));
#445=CARTESIAN_POINT('',(34.8807729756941,20.0997260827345,-10.0540279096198));
#446=CARTESIAN_POINT('',(34.7766965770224,20.1446234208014,-10.0180736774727));
#447=CARTESIAN_POINT('',(34.5591532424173,20.217581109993,-9.9601490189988));
#448=CARTESIAN_POINT('',(34.4456960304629,20.2456586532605,-9.93816431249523));
#449=CARTESIAN_POINT('',(34.2310532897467,20.2798029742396,-9.91150655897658));
#450=CARTESIAN_POINT('',(34.1305390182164,20.2885138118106,-9.90475177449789));
#451=CARTESIAN_POINT('',(33.9291977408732,20.2913686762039,-9.90253351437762));
#452=CARTESIAN_POINT('',(33.8283709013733,20.2855194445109,-9.90706481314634));
#453=CARTESIAN_POINT('',(33.6367091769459,20.2605900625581,-9.9264973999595));
#454=CARTESIAN_POINT('',(33.5456695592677,20.2424669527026,-9.94064885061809));
#455=CARTESIAN_POINT('',(33.3685171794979,20.1950573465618,-9.97800381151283));
#456=CARTESIAN_POINT('',(33.2824045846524,20.1657704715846,-10.0012076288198));
#457=CARTESIAN_POINT('',(33.1135138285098,20.0961520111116,-10.057031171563));
#458=CARTESIAN_POINT('',(33.0310203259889,20.0554141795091,-10.0900002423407));
#459=CARTESIAN_POINT('',(32.8746936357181,19.9654928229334,-10.1638885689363));
#460=CARTESIAN_POINT('',(32.8008635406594,19.916306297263,-10.2048106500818));
#461=CARTESIAN_POINT('',(32.6534235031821,19.8045812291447,-10.2993903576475));
#462=CARTESIAN_POINT('',(32.5811251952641,19.7411373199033,-10.3540156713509));
#463=CARTESIAN_POINT('',(32.4486495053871,19.6086416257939,-10.4705997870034));
#464=CARTESIAN_POINT('',(32.388480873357,19.539585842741,-10.5325638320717));
#465=CARTESIAN_POINT('',(32.2492802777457,19.3582334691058,-10.6991263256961));
#466=CARTESIAN_POINT('',(32.1786764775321,19.2434643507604,-10.8081002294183));
#467=CARTESIAN_POINT('',(32.0630489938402,19.0117757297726,-11.0368323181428));
#468=CARTESIAN_POINT('',(32.0180803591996,18.8948521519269,-11.1566130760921));
#469=CARTESIAN_POINT('',(31.9600317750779,18.6960820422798,-11.3684940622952));
#470=CARTESIAN_POINT('',(31.9415129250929,18.6137519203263,-11.458733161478));
#471=CARTESIAN_POINT('',(31.9146193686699,18.4509240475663,-11.6423762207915));
#472=CARTESIAN_POINT('',(31.9062490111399,18.3704270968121,-11.7357815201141));
#473=CARTESIAN_POINT('',(31.8986074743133,18.211798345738,-11.9252394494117));
#474=CARTESIAN_POINT('',(31.8993553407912,18.1336718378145,-12.02129720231));
#475=CARTESIAN_POINT('',(31.909092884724,17.9803767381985,-12.215348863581));
#476=CARTESIAN_POINT('',(31.9180847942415,17.9052089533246,-12.3133432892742));
#477=CARTESIAN_POINT('',(31.9484796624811,17.7297495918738,-12.548910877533));
#478=CARTESIAN_POINT('',(31.9733332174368,17.6309580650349,-12.6871627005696));
#479=CARTESIAN_POINT('',(32.0359410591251,17.4401097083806,-12.9654428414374));
#480=CARTESIAN_POINT('',(32.073702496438,17.3480566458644,-13.1054721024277));
#481=CARTESIAN_POINT('',(32.1611160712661,17.1712270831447,-13.3858891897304));
#482=CARTESIAN_POINT('',(32.2107391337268,17.0864334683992,-13.5262753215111));
#483=CARTESIAN_POINT('',(32.3216490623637,16.9241337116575,-13.8065398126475));
#484=CARTESIAN_POINT('',(32.3829282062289,16.8466227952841,-13.9464184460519));
#485=CARTESIAN_POINT('',(32.5065310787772,16.7114833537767,-14.2008953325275));
#486=CARTESIAN_POINT('',(32.56695979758,16.6526994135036,-14.3158028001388));
#487=CARTESIAN_POINT('',(32.6976826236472,16.5404745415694,-14.5431696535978));
#488=CARTESIAN_POINT('',(32.768001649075,16.4870477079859,-14.6556220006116));
#489=CARTESIAN_POINT('',(32.8829587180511,16.4112939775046,-14.8208015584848));
#490=CARTESIAN_POINT('',(32.9231199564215,16.3866431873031,-14.8755872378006));
#491=CARTESIAN_POINT('',(33.0070345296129,16.3391136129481,-14.9831227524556));
#492=CARTESIAN_POINT('',(33.0507860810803,16.316233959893,-15.0358735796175));
#493=CARTESIAN_POINT('',(33.14233999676,16.2726083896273,-15.1382052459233));
#494=CARTESIAN_POINT('',(33.1901217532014,16.2518526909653,-15.1878001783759));
#495=CARTESIAN_POINT('',(33.2907363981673,16.2128182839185,-15.282583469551));
#496=CARTESIAN_POINT('',(33.3435597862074,16.1945350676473,-15.327779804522));
#497=CARTESIAN_POINT('',(33.4401195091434,16.1657201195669,-15.4000154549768));
#498=CARTESIAN_POINT('',(33.4824207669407,16.1544325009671,-15.4286501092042));
#499=CARTESIAN_POINT('',(33.5706045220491,16.1340245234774,-15.4808751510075));
#500=CARTESIAN_POINT('',(33.6164876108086,16.1249045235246,-15.5044647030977));
#501=CARTESIAN_POINT('',(33.7124436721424,16.1093604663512,-15.5449251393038));
#502=CARTESIAN_POINT('',(33.7625665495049,16.1029761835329,-15.5616967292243));
#503=CARTESIAN_POINT('',(33.8653340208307,16.09384669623,-15.5857480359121));
#504=CARTESIAN_POINT('',(33.9179716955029,16.0910920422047,-15.5930523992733));
#505=CARTESIAN_POINT('',(34.0174242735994,16.0897076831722,-15.5967198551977));
#506=CARTESIAN_POINT('',(34.0641904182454,16.0906280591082,-15.5942763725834));
#507=CARTESIAN_POINT('',(34.1564727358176,16.0954799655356,-15.5814486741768));
#508=CARTESIAN_POINT('',(34.2019873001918,16.0994151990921,-15.5710546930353));
#509=CARTESIAN_POINT('',(34.3013215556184,16.1111440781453,-15.5402783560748));
#510=CARTESIAN_POINT('',(34.3544835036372,16.1196412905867,-15.5180867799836));
#511=CARTESIAN_POINT('',(34.4564332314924,16.1396935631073,-15.466303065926));
#512=CARTESIAN_POINT('',(34.5052103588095,16.1512558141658,-15.4366935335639));
#513=CARTESIAN_POINT('',(34.5937083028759,16.1753614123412,-15.3757510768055));
#514=CARTESIAN_POINT('',(34.6338435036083,16.1876779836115,-15.3449169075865));
#515=CARTESIAN_POINT('',(34.7111518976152,16.2138120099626,-15.2802852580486));
#516=CARTESIAN_POINT('',(34.7483225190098,16.2276307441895,-15.2464852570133));
#517=CARTESIAN_POINT('',(34.8560906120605,16.2710027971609,-15.1417608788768));
#518=CARTESIAN_POINT('',(34.9227960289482,16.3024287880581,-15.0676226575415));
#519=CARTESIAN_POINT('',(35.0559206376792,16.3731851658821,-14.9052652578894));
#520=CARTESIAN_POINT('',(35.1212987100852,16.4130123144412,-14.8164349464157));
#521=CARTESIAN_POINT('',(35.2442408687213,16.4968163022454,-14.6352855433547));
#522=CARTESIAN_POINT('',(35.3017961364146,16.540797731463,-14.5429626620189));
#523=CARTESIAN_POINT('',(35.4103940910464,16.6326381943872,-14.3560848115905));
#524=CARTESIAN_POINT('',(35.4614192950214,16.6805070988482,-14.2615246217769));
#525=CARTESIAN_POINT('',(35.5574926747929,16.7798395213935,-14.0712530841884));
#526=CARTESIAN_POINT('',(35.6025395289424,16.8313038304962,-13.9755414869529));
#527=CARTESIAN_POINT('',(35.7074136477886,16.9634097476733,-13.7372076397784));
#528=CARTESIAN_POINT('',(35.7638752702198,17.0461410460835,-13.5942491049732));
#529=CARTESIAN_POINT('',(35.8646655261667,17.2190559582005,-13.3084330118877));
#530=CARTESIAN_POINT('',(35.9089860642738,17.3092444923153,-13.1655755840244));
#531=CARTESIAN_POINT('',(35.9846343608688,17.4963501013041,-12.8818015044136));
#532=CARTESIAN_POINT('',(36.0160208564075,17.5932343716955,-12.7408789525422));
#533=CARTESIAN_POINT('',(36.0648004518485,17.793645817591,-12.4614810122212));
#534=CARTESIAN_POINT('',(36.0822089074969,17.8971655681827,-12.3230031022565));
#535=CARTESIAN_POINT('',(36.0944283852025,18.0342349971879,-12.1471010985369));
#536=CARTESIAN_POINT('',(36.0965021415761,18.0650709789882,-12.1079938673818));
#537=CARTESIAN_POINT('',(36.0992886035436,18.1272469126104,-12.0300628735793));
#538=CARTESIAN_POINT('',(36.0999998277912,18.1585873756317,-11.9912394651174));
#539=CARTESIAN_POINT('',(36.1,18.1901536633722,-11.9525931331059));
#540=B_SPLINE_CURVE_WITH_KNOTS('',3,(#428,#429,#430,#431,#432,#433,#434,#435,#436,#437,#438,
#439,#440,#441,#442,#443,#444,#445,#446,#447,#448,#449,#450,#451,#452,#453,#454,#455,#456,#457,
#458,#459,#460,#461,#462,#463,#464,#465,#466,#467,#468,#469,#470,#471,#472,#473,#474,#475,#476,
#477,#478,#479,#480,#481,#482,#483,#484,#485,#486,#487,#488,#489,#490,#491,#492,#493,#494,#495,
#496,#497,#498,#499,#500,#501,#502,#503,#504,#505,#506,#507,#508,#509,#510,#511,#512,#513,#514,
#515,#516,#517,#518,#519,#520,#521,#522,#523,#524,#525,#526,#527,#528,#529,#530,#531,#532,#533,
#534,#535,#536,#537,#538,#539),.UNSPECIFIED.,.T.,.F.,(4,2,2,2,2,2,2,2,2,2,2,2,2,2,2,2,2,2,2,2,2,
2,2,2,2,2,2,2,2,2,2,2,2,2,2,2,2,2,2,2,2,2,2,2,2,2,2,2,2,2,2,2,2,2,2,4),(0.,0.354821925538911,
0.709850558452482,1.06478313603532,1.41942979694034,1.84446916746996,2.26877019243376,
2.62034948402,2.97189439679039,3.32644530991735,3.6806332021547,3.98236309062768,
4.28395330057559,4.56438465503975,4.84482552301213,5.13685035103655,5.42897911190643,
5.75961189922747,6.09048234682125,6.60747457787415,7.12557285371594,7.49574693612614,
7.86607959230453,8.23718591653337,8.60839274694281,9.12286436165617,9.63762144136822,
10.15112946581,10.6642984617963,11.0914931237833,11.5197840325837,11.7364714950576,
11.9530519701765,12.1685853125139,12.3837202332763,12.5403530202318,12.697011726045,
12.8558765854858,13.0143270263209,13.1540104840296,13.2938657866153,13.4675871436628,
13.6417197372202,13.7977587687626,13.9539317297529,14.2668418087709,14.618178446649,
14.9699079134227,15.3225601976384,15.6752903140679,16.1983356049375,16.7217288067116,
17.24271822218,17.7631345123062,17.9126540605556,18.0623360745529),.UNSPECIFIED.);
#541=CARTESIAN_POINT('',(36.1,18.1901536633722,-11.9525931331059));
#542=VERTEX_POINT('',#541);
#543=EDGE_CURVE('E182',#542,#542,#540,.T.);
#544=ORIENTED_EDGE('',*,*,#543,.F.);
#545=EDGE_LOOP('',(#544));
#546=FACE_BOUND('',#545,.T.);
#547=CARTESIAN_POINT('',(34.,18.1901536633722,-5.));
#548=DIRECTION('',(0.,0.,1.));
#549=DIRECTION('',(1.,0.,0.));
#550=AXIS2_PLACEMENT_3D('',#547,#548,#549);
#551=CIRCLE('',#550,2.1);
#552=CARTESIAN_POINT('',(36.1,18.1901536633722,-5.));
#553=VERTEX_POINT('',#552);
#554=EDGE_CURVE('E429',#553,#553,#551,.F.);
#555=ORIENTED_EDGE('',*,*,#554,.F.);
#556=EDGE_LOOP('',(#555));
#557=FACE_BOUND('',#556,.T.);
#558=ADVANCED_FACE('F393',(#546,#557),#427,.F.);
#559=CARTESIAN_POINT('',(50.,0.,0.500000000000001));
#560=DIRECTION('',(-1.,0.,0.));
#561=DIRECTION('',(0.,0.,1.));
#562=AXIS2_PLACEMENT_3D('',#559,#560,#561);
#563=CYLINDRICAL_SURFACE('',#562,12.7);
#564=CARTESIAN_POINT('',(6.9,0.,-12.2));
#565=CARTESIAN_POINT('',(6.90000470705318,0.117101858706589,-12.1999980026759));
#566=CARTESIAN_POINT('',(6.90982797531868,0.234267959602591,-12.1983634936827));
#567=CARTESIAN_POINT('',(6.94884569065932,0.465314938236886,-12.192000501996));
#568=CARTESIAN_POINT('',(6.97805803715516,0.579192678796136,-12.1872691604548));
#569=CARTESIAN_POINT('',(7.05494854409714,0.80028665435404,-12.1752432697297));
#570=CARTESIAN_POINT('',(7.10261169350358,0.907508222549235,-12.167950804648));
#571=CARTESIAN_POINT('',(7.21501173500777,1.11241820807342,-12.1516048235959));
#572=CARTESIAN_POINT('',(7.27974664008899,1.21010773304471,-12.1425515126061));
#573=CARTESIAN_POINT('',(7.42510112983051,1.39411436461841,-12.1235923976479));
#574=CARTESIAN_POINT('',(7.50584998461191,1.4803286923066,-12.1136800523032));
#575=CARTESIAN_POINT('',(7.68066197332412,1.6380498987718,-12.0941702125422));
#576=CARTESIAN_POINT('',(7.77472594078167,1.70955585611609,-12.0845727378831));
#577=CARTESIAN_POINT('',(7.97420276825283,1.8362414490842,-12.0667159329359));
#578=CARTESIAN_POINT('',(8.07968088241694,1.89131963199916,-12.058465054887));
#579=CARTESIAN_POINT('',(8.2985509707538,1.98293746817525,-12.0443262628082));
#580=CARTESIAN_POINT('',(8.41194241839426,2.01947835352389,-12.0384381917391));
#581=CARTESIAN_POINT('',(8.64233163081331,2.07266088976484,-12.0297567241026));
#582=CARTESIAN_POINT('',(8.75928740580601,2.08947985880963,-12.0269357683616));
#583=CARTESIAN_POINT('',(8.9943924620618,2.10329087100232,-12.0246245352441));
#584=CARTESIAN_POINT('',(9.11254165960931,2.10028429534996,-12.0251340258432));
#585=CARTESIAN_POINT('',(9.34541503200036,2.07467403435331,-12.0294009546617));
#586=CARTESIAN_POINT('',(9.46016178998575,2.05226940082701,-12.0331254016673));
#587=CARTESIAN_POINT('',(9.68424485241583,1.98881132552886,-12.0433509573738));
#588=CARTESIAN_POINT('',(9.7935809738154,1.94775725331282,-12.0498521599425));
#589=CARTESIAN_POINT('',(10.004335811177,1.84796343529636,-12.0649344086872));
#590=CARTESIAN_POINT('',(10.1057146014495,1.7891408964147,-12.0735251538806));
#591=CARTESIAN_POINT('',(10.2972382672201,1.65553869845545,-12.0918117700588));
#592=CARTESIAN_POINT('',(10.3873822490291,1.58075777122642,-12.1015077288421));
#593=CARTESIAN_POINT('',(10.5550297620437,1.41627635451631,-12.1210573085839));
#594=CARTESIAN_POINT('',(10.6323657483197,1.32640505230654,-12.1309114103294));
#595=CARTESIAN_POINT('',(10.7708848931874,1.13487206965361,-12.1495576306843));
#596=CARTESIAN_POINT('',(10.8320679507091,1.03321031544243,-12.1583497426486));
#597=CARTESIAN_POINT('',(10.936559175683,0.82082571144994,-12.1738935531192));
#598=CARTESIAN_POINT('',(10.979852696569,0.710095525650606,-12.1806435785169));
#599=CARTESIAN_POINT('',(11.0471812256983,0.482799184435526,-12.1913291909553));
#600=CARTESIAN_POINT('',(11.071217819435,0.366233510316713,-12.1952650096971));
#601=CARTESIAN_POINT('',(11.0991234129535,0.132019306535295,-12.199847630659));
#602=CARTESIAN_POINT('',(11.1032224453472,0.0143988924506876,-12.200531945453));
#603=CARTESIAN_POINT('',(11.0917496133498,-0.219848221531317,-12.1986371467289));
#604=CARTESIAN_POINT('',(11.0761784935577,-0.336474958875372,-12.1960581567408));
#605=CARTESIAN_POINT('',(11.0259986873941,-0.564714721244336,-12.1879497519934));
#606=CARTESIAN_POINT('',(10.9915037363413,-0.676353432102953,-12.1824379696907));
#607=CARTESIAN_POINT('',(10.904576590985,-0.892263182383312,-12.1690795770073));
#608=CARTESIAN_POINT('',(10.8521434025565,-0.996533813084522,-12.161232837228));
#609=CARTESIAN_POINT('',(10.7303002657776,-1.19574773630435,-12.1439820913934));
#610=CARTESIAN_POINT('',(10.6607464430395,-1.29060188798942,-12.1345651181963));
#611=CARTESIAN_POINT('',(10.5068345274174,-1.4673739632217,-12.1152580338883));
#612=CARTESIAN_POINT('',(10.4224753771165,-1.5492909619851,-12.1053678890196));
#613=CARTESIAN_POINT('',(10.2403163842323,-1.69871479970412,-12.0861080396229));
#614=CARTESIAN_POINT('',(10.1423883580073,-1.76606631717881,-12.0767446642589));
#615=CARTESIAN_POINT('',(9.93647328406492,-1.88336299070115,-12.0597162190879));
#616=CARTESIAN_POINT('',(9.82848655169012,-1.93330869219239,-12.0520510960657));
#617=CARTESIAN_POINT('',(9.60595607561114,-2.01414296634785,-12.0393343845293));
#618=CARTESIAN_POINT('',(9.49144118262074,-2.04510921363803,-12.034272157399));
#619=CARTESIAN_POINT('',(9.25874479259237,-2.08735022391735,-12.0273075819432));
#620=CARTESIAN_POINT('',(9.14056360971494,-2.09862666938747,-12.0254049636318));
#621=CARTESIAN_POINT('',(8.90544012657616,-2.10112162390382,-12.0249865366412));
#622=CARTESIAN_POINT('',(8.78850042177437,-2.09258459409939,-12.0264294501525));
#623=CARTESIAN_POINT('',(8.55774555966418,-2.05622314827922,-12.0324491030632));
#624=CARTESIAN_POINT('',(8.44393039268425,-2.02839879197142,-12.0370258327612));
#625=CARTESIAN_POINT('',(8.22274773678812,-1.95434558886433,-12.0487818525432));
#626=CARTESIAN_POINT('',(8.11537314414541,-1.90813746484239,-12.055958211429));
#627=CARTESIAN_POINT('',(7.90986076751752,-1.79865345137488,-12.0721077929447));
#628=CARTESIAN_POINT('',(7.81172343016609,-1.73537673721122,-12.0810811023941));
#629=CARTESIAN_POINT('',(7.62623566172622,-1.59267798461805,-12.0999445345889));
#630=CARTESIAN_POINT('',(7.53902461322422,-1.5130759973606,-12.1098441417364));
#631=CARTESIAN_POINT('',(7.3791139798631,-1.34036583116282,-12.1293687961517));
#632=CARTESIAN_POINT('',(7.30641775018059,-1.24725453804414,-12.138993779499));
#633=CARTESIAN_POINT('',(7.17715018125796,-1.04941831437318,-12.1569603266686));
#634=CARTESIAN_POINT('',(7.12069163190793,-0.944618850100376,-12.1652927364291));
#635=CARTESIAN_POINT('',(7.02626696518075,-0.726928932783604,-12.1796461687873));
#636=CARTESIAN_POINT('',(6.98828236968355,-0.614046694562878,-12.185669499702));
#637=CARTESIAN_POINT('',(6.94015916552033,-0.417266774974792,-12.1934066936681));
#638=CARTESIAN_POINT('',(6.92512350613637,-0.334561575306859,-12.1958660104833));
#639=CARTESIAN_POINT('',(6.90504231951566,-0.167915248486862,-12.1991633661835));
#640=CARTESIAN_POINT('',(6.89999662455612,-0.0839741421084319,-12.2000014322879));
#641=CARTESIAN_POINT('',(6.9,0.,-12.2));
#642=B_SPLINE_CURVE_WITH_KNOTS('',3,(#564,#565,#566,#567,#568,#569,#570,#571,#572,#573,#574,
#575,#576,#577,#578,#579,#580,#581,#582,#583,#584,#585,#586,#587,#588,#589,#590,#591,#592,#593,
#594,#595,#596,#597,#598,#599,#600,#601,#602,#603,#604,#605,#606,#607,#608,#609,#610,#611,#612,
#613,#614,#615,#616,#617,#618,#619,#620,#621,#622,#623,#624,#625,#626,#627,#628,#629,#630,#631,
#632,#633,#634,#635,#636,#637,#638,#639,#640,#641),.UNSPECIFIED.,.T.,.F.,(4,2,2,2,2,2,2,2,2,2,2,
2,2,2,2,2,2,2,2,2,2,2,2,2,2,2,2,2,2,2,2,2,2,2,2,2,2,2,4),(0.,0.350998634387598,
0.702321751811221,1.05335964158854,1.40435669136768,1.75831176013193,2.11228899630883,
2.46840905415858,2.82450543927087,3.17737502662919,3.53022003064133,3.87948668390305,
4.22876514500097,4.57969687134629,4.93065649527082,5.28589580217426,5.64113733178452,
5.99666913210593,6.3521716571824,6.70356262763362,7.05494029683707,7.40422890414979,
7.75353687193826,8.10588697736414,8.45826225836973,8.81422771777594,9.17018202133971,
9.52466965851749,9.87912700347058,10.2292342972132,10.5793405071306,10.929053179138,
11.278782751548,11.6325972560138,11.9864934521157,12.3427915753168,12.6987325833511,
12.950439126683,13.2021414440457),.UNSPECIFIED.);
#643=CARTESIAN_POINT('',(6.9,0.,-12.2));
#644=VERTEX_POINT('',#643);
#645=EDGE_CURVE('E422',#644,#644,#642,.T.);
#646=ORIENTED_EDGE('',*,*,#645,.T.);
#647=EDGE_LOOP('',(#646));
#648=FACE_BOUND('',#647,.T.);
#649=CARTESIAN_POINT('',(31.9,0.,-12.2));
#650=CARTESIAN_POINT('',(31.9000047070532,0.117101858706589,-12.1999980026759));
#651=CARTESIAN_POINT('',(31.9098279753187,0.234267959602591,-12.1983634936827));
#652=CARTESIAN_POINT('',(31.9488456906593,0.465314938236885,-12.192000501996));
#653=CARTESIAN_POINT('',(31.9780580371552,0.579192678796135,-12.1872691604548));
#654=CARTESIAN_POINT('',(32.0549485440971,0.800286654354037,-12.1752432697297));
#655=CARTESIAN_POINT('',(32.1026116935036,0.907508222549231,-12.167950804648));
#656=CARTESIAN_POINT('',(32.2150117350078,1.11241820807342,-12.1516048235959));
#657=CARTESIAN_POINT('',(32.279746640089,1.21010773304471,-12.1425515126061));
#658=CARTESIAN_POINT('',(32.4251011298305,1.39411436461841,-12.1235923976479));
#659=CARTESIAN_POINT('',(32.5058499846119,1.4803286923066,-12.1136800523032));
#660=CARTESIAN_POINT('',(32.6806619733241,1.6380498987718,-12.0941702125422));
#661=CARTESIAN_POINT('',(32.7747259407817,1.70955585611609,-12.0845727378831));
#662=CARTESIAN_POINT('',(32.9742027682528,1.8362414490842,-12.0667159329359));
#663=CARTESIAN_POINT('',(33.0796808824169,1.89131963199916,-12.058465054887));
#664=CARTESIAN_POINT('',(33.2985509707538,1.98293746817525,-12.0443262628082));
#665=CARTESIAN_POINT('',(33.4119424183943,2.01947835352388,-12.0384381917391));
#666=CARTESIAN_POINT('',(33.6423316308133,2.07266088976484,-12.0297567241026));
#667=CARTESIAN_POINT('',(33.759287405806,2.08947985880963,-12.0269357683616));
#668=CARTESIAN_POINT('',(33.9943924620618,2.10329087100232,-12.0246245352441));
#669=CARTESIAN_POINT('',(34.1125416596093,2.10028429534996,-12.0251340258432));
#670=CARTESIAN_POINT('',(34.3454150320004,2.07467403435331,-12.0294009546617));
#671=CARTESIAN_POINT('',(34.4601617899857,2.05226940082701,-12.0331254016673));
#672=CARTESIAN_POINT('',(34.6842448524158,1.98881132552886,-12.0433509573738));
#673=CARTESIAN_POINT('',(34.7935809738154,1.94775725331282,-12.0498521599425));
#674=CARTESIAN_POINT('',(35.004335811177,1.84796343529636,-12.0649344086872));
#675=CARTESIAN_POINT('',(35.1057146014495,1.7891408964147,-12.0735251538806));
#676=CARTESIAN_POINT('',(35.2972382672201,1.65553869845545,-12.0918117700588));
#677=CARTESIAN_POINT('',(35.3873822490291,1.58075777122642,-12.1015077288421));
#678=CARTESIAN_POINT('',(35.5550297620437,1.41627635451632,-12.1210573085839));
#679=CARTESIAN_POINT('',(35.6323657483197,1.32640505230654,-12.1309114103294));
#680=CARTESIAN_POINT('',(35.7708848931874,1.13487206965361,-12.1495576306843));
#681=CARTESIAN_POINT('',(35.8320679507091,1.03321031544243,-12.1583497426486));
#682=CARTESIAN_POINT('',(35.936559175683,0.820825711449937,-12.1738935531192));
#683=CARTESIAN_POINT('',(35.979852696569,0.710095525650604,-12.1806435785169));
#684=CARTESIAN_POINT('',(36.0471812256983,0.482799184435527,-12.1913291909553));
#685=CARTESIAN_POINT('',(36.071217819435,0.366233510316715,-12.1952650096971));
#686=CARTESIAN_POINT('',(36.0991234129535,0.132019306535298,-12.199847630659));
#687=CARTESIAN_POINT('',(36.1032224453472,0.0143988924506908,-12.200531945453));
#688=CARTESIAN_POINT('',(36.0917496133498,-0.219848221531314,-12.1986371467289));
#689=CARTESIAN_POINT('',(36.0761784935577,-0.336474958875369,-12.1960581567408));
#690=CARTESIAN_POINT('',(36.0259986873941,-0.564714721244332,-12.1879497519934));
#691=CARTESIAN_POINT('',(35.9915037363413,-0.676353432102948,-12.1824379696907));
#692=CARTESIAN_POINT('',(35.904576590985,-0.892263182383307,-12.1690795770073));
#693=CARTESIAN_POINT('',(35.8521434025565,-0.996533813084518,-12.161232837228));
#694=CARTESIAN_POINT('',(35.7303002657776,-1.19574773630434,-12.1439820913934));
#695=CARTESIAN_POINT('',(35.6607464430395,-1.29060188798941,-12.1345651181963));
#696=CARTESIAN_POINT('',(35.5068345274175,-1.46737396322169,-12.1152580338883));
#697=CARTESIAN_POINT('',(35.4224753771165,-1.5492909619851,-12.1053678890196));
#698=CARTESIAN_POINT('',(35.2403163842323,-1.69871479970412,-12.0861080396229));
#699=CARTESIAN_POINT('',(35.1423883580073,-1.76606631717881,-12.0767446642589));
#700=CARTESIAN_POINT('',(34.9364732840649,-1.88336299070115,-12.0597162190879));
#701=CARTESIAN_POINT('',(34.8284865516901,-1.93330869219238,-12.0520510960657));
#702=CARTESIAN_POINT('',(34.6059560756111,-2.01414296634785,-12.0393343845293));
#703=CARTESIAN_POINT('',(34.4914411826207,-2.04510921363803,-12.034272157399));
#704=CARTESIAN_POINT('',(34.2587447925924,-2.08735022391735,-12.0273075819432));
#705=CARTESIAN_POINT('',(34.1405636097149,-2.09862666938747,-12.0254049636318));
#706=CARTESIAN_POINT('',(33.9054401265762,-2.10112162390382,-12.0249865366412));
#707=CARTESIAN_POINT('',(33.7885004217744,-2.09258459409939,-12.0264294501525));
#708=CARTESIAN_POINT('',(33.5577455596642,-2.05622314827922,-12.0324491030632));
#709=CARTESIAN_POINT('',(33.4439303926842,-2.02839879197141,-12.0370258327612));
#710=CARTESIAN_POINT('',(33.2227477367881,-1.95434558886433,-12.0487818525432));
#711=CARTESIAN_POINT('',(33.1153731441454,-1.90813746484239,-12.055958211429));
#712=CARTESIAN_POINT('',(32.9098607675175,-1.79865345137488,-12.0721077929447));
#713=CARTESIAN_POINT('',(32.8117234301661,-1.73537673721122,-12.0810811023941));
#714=CARTESIAN_POINT('',(32.6262356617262,-1.59267798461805,-12.0999445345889));
#715=CARTESIAN_POINT('',(32.5390246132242,-1.5130759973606,-12.1098441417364));
#716=CARTESIAN_POINT('',(32.3791139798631,-1.34036583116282,-12.1293687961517));
#717=CARTESIAN_POINT('',(32.3064177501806,-1.24725453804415,-12.138993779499));
#718=CARTESIAN_POINT('',(32.177150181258,-1.04941831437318,-12.1569603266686));
#719=CARTESIAN_POINT('',(32.1206916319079,-0.944618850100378,-12.1652927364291));
#720=CARTESIAN_POINT('',(32.0262669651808,-0.726928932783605,-12.1796461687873));
#721=CARTESIAN_POINT('',(31.9882823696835,-0.614046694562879,-12.185669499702));
#722=CARTESIAN_POINT('',(31.9401591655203,-0.417266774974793,-12.1934066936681));
#723=CARTESIAN_POINT('',(31.9251235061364,-0.334561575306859,-12.1958660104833));
#724=CARTESIAN_POINT('',(31.9050423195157,-0.167915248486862,-12.1991633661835));
#725=CARTESIAN_POINT('',(31.8999966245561,-0.0839741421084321,-12.2000014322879));
#726=CARTESIAN_POINT('',(31.9,0.,-12.2));
#727=B_SPLINE_CURVE_WITH_KNOTS('',3,(#649,#650,#651,#652,#653,#654,#655,#656,#657,#658,#659,
#660,#661,#662,#663,#664,#665,#666,#667,#668,#669,#670,#671,#672,#673,#674,#675,#676,#677,#678,
#679,#680,#681,#682,#683,#684,#685,#686,#687,#688,#689,#690,#691,#692,#693,#694,#695,#696,#697,
#698,#699,#700,#701,#702,#703,#704,#705,#706,#707,#708,#709,#710,#711,#712,#713,#714,#715,#716,
#717,#718,#719,#720,#721,#722,#723,#724,#725,#726),.UNSPECIFIED.,.T.,.F.,(4,2,2,2,2,2,2,2,2,2,2,
2,2,2,2,2,2,2,2,2,2,2,2,2,2,2,2,2,2,2,2,2,2,2,2,2,2,2,4),(0.,0.350998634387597,
0.702321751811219,1.05335964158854,1.40435669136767,1.75831176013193,2.11228899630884,
2.46840905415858,2.82450543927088,3.17737502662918,3.53022003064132,3.87948668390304,
4.22876514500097,4.57969687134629,4.93065649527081,5.28589580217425,5.64113733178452,
5.99666913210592,6.35217165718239,6.70356262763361,7.05494029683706,7.40422890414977,
7.75353687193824,8.10588697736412,8.45826225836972,8.81422771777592,9.1701820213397,
9.52466965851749,9.87912700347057,10.2292342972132,10.5793405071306,10.929053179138,
11.278782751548,11.6325972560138,11.9864934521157,12.3427915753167,12.6987325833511,
12.950439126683,13.2021414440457),.UNSPECIFIED.);
#728=CARTESIAN_POINT('',(31.9,0.,-12.2));
#729=VERTEX_POINT('',#728);
#730=EDGE_CURVE('E309',#729,#729,#727,.T.);
#731=ORIENTED_EDGE('',*,*,#730,.T.);
#732=EDGE_LOOP('',(#731));
#733=FACE_BOUND('',#732,.T.);
#734=DIRECTION('',(-1.,0.,0.));
#735=VECTOR('',#734,1.);
#736=CARTESIAN_POINT('',(50.,-12.6901536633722,0.));
#737=LINE('',#736,#735);
#738=CARTESIAN_POINT('',(43.,-12.6901536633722,0.));
#739=VERTEX_POINT('',#738);
#740=CARTESIAN_POINT('',(0.,-12.6901536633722,0.));
#741=VERTEX_POINT('',#740);
#742=EDGE_CURVE('E148',#739,#741,#737,.T.);
#743=ORIENTED_EDGE('',*,*,#742,.F.);
#744=CARTESIAN_POINT('',(43.,0.,0.500000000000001));
#745=DIRECTION('',(1.,0.,0.));
#746=DIRECTION('',(0.,0.,-1.));
#747=AXIS2_PLACEMENT_3D('',#744,#745,#746);
#748=CIRCLE('',#747,12.7);
#749=CARTESIAN_POINT('',(43.,12.6901536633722,0.));
#750=VERTEX_POINT('',#749);
#751=EDGE_CURVE('E161',#739,#750,#748,.T.);
#752=ORIENTED_EDGE('',*,*,#751,.T.);
#753=DIRECTION('',(-1.,0.,0.));
#754=VECTOR('',#753,1.);
#755=CARTESIAN_POINT('',(50.,12.6901536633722,0.));
#756=LINE('',#755,#754);
#757=CARTESIAN_POINT('',(0.,12.6901536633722,0.));
#758=VERTEX_POINT('',#757);
#759=EDGE_CURVE('E180',#750,#758,#756,.T.);
#760=ORIENTED_EDGE('',*,*,#759,.T.);
#761=CARTESIAN_POINT('',(0.,0.,0.500000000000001));
#762=DIRECTION('',(-1.,0.,0.));
#763=DIRECTION('',(0.,0.,-1.));
#764=AXIS2_PLACEMENT_3D('',#761,#762,#763);
#765=CIRCLE('',#764,12.7);
#766=EDGE_CURVE('E167',#758,#741,#765,.T.);
#767=ORIENTED_EDGE('',*,*,#766,.T.);
#768=EDGE_LOOP('',(#743,#752,#760,#767));
#769=FACE_BOUND('',#768,.T.);
#770=ADVANCED_FACE('F174',(#648,#733,#769),#563,.F.);
#771=CARTESIAN_POINT('',(50.,-23.6901536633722,0.));
#772=DIRECTION('',(0.,1.,0.));
#773=DIRECTION('',(0.,0.,1.));
#774=AXIS2_PLACEMENT_3D('',#771,#772,#773);
#775=PLANE('',#774);
#776=DIRECTION('',(-1.,0.,0.));
#777=VECTOR('',#776,1.);
#778=CARTESIAN_POINT('',(50.,-23.6901536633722,-8.));
#779=LINE('',#778,#777);
#780=CARTESIAN_POINT('',(45.,-23.6901536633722,-8.));
#781=VERTEX_POINT('',#780);
#782=CARTESIAN_POINT('',(0.,-23.6901536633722,-8.));
#783=VERTEX_POINT('',#782);
#784=EDGE_CURVE('E218',#781,#783,#779,.T.);
#785=ORIENTED_EDGE('',*,*,#784,.F.);
#786=DIRECTION('',(0.,0.,-1.));
#787=VECTOR('',#786,1.);
#788=CARTESIAN_POINT('',(45.,-23.6901536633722,0.));
#789=LINE('',#788,#787);
#790=CARTESIAN_POINT('',(45.,-23.6901536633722,0.));
#791=VERTEX_POINT('',#790);
#792=EDGE_CURVE('E552',#781,#791,#789,.F.);
#793=ORIENTED_EDGE('',*,*,#792,.T.);
#794=DIRECTION('',(-1.,0.,0.));
#795=VECTOR('',#794,1.);
#796=CARTESIAN_POINT('',(50.,-23.6901536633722,0.));
#797=LINE('',#796,#795);
#798=CARTESIAN_POINT('',(0.,-23.6901536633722,0.));
#799=VERTEX_POINT('',#798);
#800=EDGE_CURVE('E165',#791,#799,#797,.T.);
#801=ORIENTED_EDGE('',*,*,#800,.T.);
#802=DIRECTION('',(0.,0.,-1.));
#803=VECTOR('',#802,1.);
#804=CARTESIAN_POINT('',(0.,-23.6901536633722,0.));
#805=LINE('',#804,#803);
#806=EDGE_CURVE('E175',#799,#783,#805,.T.);
#807=ORIENTED_EDGE('',*,*,#806,.T.);
#808=EDGE_LOOP('',(#785,#793,#801,#807));
#809=FACE_BOUND('',#808,.T.);
#810=ADVANCED_FACE('F553',(#809),#775,.F.);
#811=CARTESIAN_POINT('',(50.,-28.2874518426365,-20.2));
#812=DIRECTION('',(-1.,0.,0.));
#813=DIRECTION('',(0.,0.,1.));
#814=AXIS2_PLACEMENT_3D('',#811,#812,#813);
#815=CYLINDRICAL_SURFACE('',#814,13.0374518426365);
#816=ORIENTED_EDGE('',*,*,#407,.T.);
#817=EDGE_LOOP('',(#816));
#818=FACE_BOUND('',#817,.T.);
#819=ORIENTED_EDGE('',*,*,#273,.T.);
#820=EDGE_LOOP('',(#819));
#821=FACE_BOUND('',#820,.T.);
#822=DIRECTION('',(-1.,0.,0.));
#823=VECTOR('',#822,1.);
#824=CARTESIAN_POINT('',(50.,-15.7609123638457,-16.5860050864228));
#825=LINE('',#824,#823);
#826=CARTESIAN_POINT('',(0.,-15.7609123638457,-16.5860050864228));
#827=VERTEX_POINT('',#826);
#828=CARTESIAN_POINT('',(45.,-15.7609123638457,-16.5860050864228));
#829=VERTEX_POINT('',#828);
#830=EDGE_CURVE('E64',#827,#829,#825,.F.);
#831=ORIENTED_EDGE('',*,*,#830,.T.);
#832=CARTESIAN_POINT('',(45.,-28.2874518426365,-20.2));
#833=DIRECTION('',(1.,0.,0.));
#834=DIRECTION('',(0.,0.,-1.));
#835=AXIS2_PLACEMENT_3D('',#832,#833,#834);
#836=CIRCLE('',#835,13.0374518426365);
#837=EDGE_CURVE('E496',#829,#781,#836,.T.);
#838=ORIENTED_EDGE('',*,*,#837,.T.);
#839=ORIENTED_EDGE('',*,*,#784,.T.);
#840=CARTESIAN_POINT('',(0.,-28.2874518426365,-20.2));
#841=DIRECTION('',(-1.,0.,0.));
#842=DIRECTION('',(0.,0.,1.));
#843=AXIS2_PLACEMENT_3D('',#840,#841,#842);
#844=CIRCLE('',#843,13.0374518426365);
#845=EDGE_CURVE('E188',#783,#827,#844,.T.);
#846=ORIENTED_EDGE('',*,*,#845,.T.);
#847=EDGE_LOOP('',(#831,#838,#839,#846));
#848=FACE_BOUND('',#847,.T.);
#849=ADVANCED_FACE('F480',(#818,#821,#848),#815,.F.);
#850=CARTESIAN_POINT('',(50.,-15.25,-20.2));
#851=DIRECTION('',(0.,0.,1.));
#852=DIRECTION('',(1.,0.,0.));
#853=AXIS2_PLACEMENT_3D('',#850,#851,#852);
#854=PLANE('',#853);
#855=CARTESIAN_POINT('',(9.,0.,-20.2));
#856=DIRECTION('',(0.,0.,-1.));
#857=DIRECTION('',(-1.,0.,0.));
#858=AXIS2_PLACEMENT_3D('',#855,#856,#857);
#859=CIRCLE('',#858,6.);
#860=CARTESIAN_POINT('',(3.,0.,-20.2));
#861=VERTEX_POINT('',#860);
#862=EDGE_CURVE('E271',#861,#861,#859,.T.);
#863=ORIENTED_EDGE('',*,*,#862,.F.);
#864=EDGE_LOOP('',(#863));
#865=FACE_BOUND('',#864,.T.);
#866=CARTESIAN_POINT('',(34.,0.,-20.2));
#867=DIRECTION('',(0.,0.,-1.));
#868=DIRECTION('',(-1.,0.,0.));
#869=AXIS2_PLACEMENT_3D('',#866,#867,#868);
#870=CIRCLE('',#869,6.);
#871=CARTESIAN_POINT('',(28.,0.,-20.2));
#872=VERTEX_POINT('',#871);
#873=EDGE_CURVE('E366',#872,#872,#870,.T.);
#874=ORIENTED_EDGE('',*,*,#873,.F.);
#875=EDGE_LOOP('',(#874));
#876=FACE_BOUND('',#875,.T.);
#877=DIRECTION('',(0.,1.,0.));
#878=VECTOR('',#877,1.);
#879=CARTESIAN_POINT('',(0.,-15.25,-20.2));
#880=LINE('',#879,#878);
#881=CARTESIAN_POINT('',(0.,-10.9568526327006,-20.2));
#882=VERTEX_POINT('',#881);
#883=CARTESIAN_POINT('',(0.,10.9568526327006,-20.2));
#884=VERTEX_POINT('',#883);
#885=EDGE_CURVE('E195',#882,#884,#880,.T.);
#886=ORIENTED_EDGE('',*,*,#885,.T.);
#887=DIRECTION('',(-1.,0.,0.));
#888=VECTOR('',#887,1.);
#889=CARTESIAN_POINT('',(50.,10.9568526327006,-20.2));
#890=LINE('',#889,#888);
#891=CARTESIAN_POINT('',(45.,10.9568526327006,-20.2));
#892=VERTEX_POINT('',#891);
#893=EDGE_CURVE('E485',#884,#892,#890,.F.);
#894=ORIENTED_EDGE('',*,*,#893,.T.);
#895=DIRECTION('',(0.,1.,0.));
#896=VECTOR('',#895,1.);
#897=CARTESIAN_POINT('',(45.,-15.25,-20.2));
#898=LINE('',#897,#896);
#899=CARTESIAN_POINT('',(45.,-10.9568526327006,-20.2));
#900=VERTEX_POINT('',#899);
#901=EDGE_CURVE('E495',#892,#900,#898,.F.);
#902=ORIENTED_EDGE('',*,*,#901,.T.);
#903=DIRECTION('',(-1.,0.,0.));
#904=VECTOR('',#903,1.);
#905=CARTESIAN_POINT('',(50.,-10.9568526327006,-20.2));
#906=LINE('',#905,#904);
#907=EDGE_CURVE('E483',#900,#882,#906,.T.);
#908=ORIENTED_EDGE('',*,*,#907,.T.);
#909=EDGE_LOOP('',(#886,#894,#902,#908));
#910=FACE_BOUND('',#909,.T.);
#911=ADVANCED_FACE('F377',(#865,#876,#910),#854,.F.);
#912=CARTESIAN_POINT('',(50.,28.2874518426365,-20.2));
#913=DIRECTION('',(-1.,0.,0.));
#914=DIRECTION('',(0.,0.,1.));
#915=AXIS2_PLACEMENT_3D('',#912,#913,#914);
#916=CYLINDRICAL_SURFACE('',#915,13.0374518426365);
#917=ORIENTED_EDGE('',*,*,#543,.T.);
#918=EDGE_LOOP('',(#917));
#919=FACE_BOUND('',#918,.T.);
#920=ORIENTED_EDGE('',*,*,#139,.T.);
#921=EDGE_LOOP('',(#920));
#922=FACE_BOUND('',#921,.T.);
#923=DIRECTION('',(-1.,0.,0.));
#924=VECTOR('',#923,1.);
#925=CARTESIAN_POINT('',(50.,23.6901536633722,-8.));
#926=LINE('',#925,#924);
#927=CARTESIAN_POINT('',(45.,23.6901536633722,-8.));
#928=VERTEX_POINT('',#927);
#929=CARTESIAN_POINT('',(0.,23.6901536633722,-8.));
#930=VERTEX_POINT('',#929);
#931=EDGE_CURVE('E211',#928,#930,#926,.T.);
#932=ORIENTED_EDGE('',*,*,#931,.F.);
#933=CARTESIAN_POINT('',(45.,28.2874518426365,-20.2));
#934=DIRECTION('',(1.,0.,0.));
#935=DIRECTION('',(0.,0.,-1.));
#936=AXIS2_PLACEMENT_3D('',#933,#934,#935);
#937=CIRCLE('',#936,13.0374518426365);
#938=CARTESIAN_POINT('',(45.,15.7609123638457,-16.5860050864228));
#939=VERTEX_POINT('',#938);
#940=EDGE_CURVE('E518',#928,#939,#937,.T.);
#941=ORIENTED_EDGE('',*,*,#940,.T.);
#942=DIRECTION('',(-1.,0.,0.));
#943=VECTOR('',#942,1.);
#944=CARTESIAN_POINT('',(50.,15.7609123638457,-16.5860050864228));
#945=LINE('',#944,#943);
#946=CARTESIAN_POINT('',(0.,15.7609123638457,-16.5860050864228));
#947=VERTEX_POINT('',#946);
#948=EDGE_CURVE('E507',#939,#947,#945,.T.);
#949=ORIENTED_EDGE('',*,*,#948,.T.);
#950=CARTESIAN_POINT('',(0.,28.2874518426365,-20.2));
#951=DIRECTION('',(-1.,0.,0.));
#952=DIRECTION('',(0.,0.,-1.));
#953=AXIS2_PLACEMENT_3D('',#950,#951,#952);
#954=CIRCLE('',#953,13.0374518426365);
#955=EDGE_CURVE('E199',#947,#930,#954,.T.);
#956=ORIENTED_EDGE('',*,*,#955,.T.);
#957=EDGE_LOOP('',(#932,#941,#949,#956));
#958=FACE_BOUND('',#957,.T.);
#959=ADVANCED_FACE('F373',(#919,#922,#958),#916,.F.);
#960=CARTESIAN_POINT('',(50.,23.6901536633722,0.));
#961=DIRECTION('',(0.,-1.,0.));
#962=DIRECTION('',(0.,0.,-1.));
#963=AXIS2_PLACEMENT_3D('',#960,#961,#962);
#964=PLANE('',#963);
#965=DIRECTION('',(-1.,0.,0.));
#966=VECTOR('',#965,1.);
#967=CARTESIAN_POINT('',(50.,23.6901536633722,0.));
#968=LINE('',#967,#966);
#969=CARTESIAN_POINT('',(45.,23.6901536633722,0.));
#970=VERTEX_POINT('',#969);
#971=CARTESIAN_POINT('',(0.,23.6901536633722,0.));
#972=VERTEX_POINT('',#971);
#973=EDGE_CURVE('E209',#970,#972,#968,.T.);
#974=ORIENTED_EDGE('',*,*,#973,.F.);
#975=DIRECTION('',(0.,0.,1.));
#976=VECTOR('',#975,1.);
#977=CARTESIAN_POINT('',(45.,23.6901536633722,-8.));
#978=LINE('',#977,#976);
#979=EDGE_CURVE('E515',#970,#928,#978,.F.);
#980=ORIENTED_EDGE('',*,*,#979,.T.);
#981=ORIENTED_EDGE('',*,*,#931,.T.);
#982=DIRECTION('',(0.,0.,1.));
#983=VECTOR('',#982,1.);
#984=CARTESIAN_POINT('',(0.,23.6901536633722,0.));
#985=LINE('',#984,#983);
#986=EDGE_CURVE('E196',#930,#972,#985,.T.);
#987=ORIENTED_EDGE('',*,*,#986,.T.);
#988=EDGE_LOOP('',(#974,#980,#981,#987));
#989=FACE_BOUND('',#988,.T.);
#990=ADVANCED_FACE('F380',(#989),#964,.F.);
#991=CARTESIAN_POINT('',(50.,12.6901536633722,0.));
#992=DIRECTION('',(0.,0.,-1.));
#993=DIRECTION('',(0.,1.,0.));
#994=AXIS2_PLACEMENT_3D('',#991,#992,#993);
#995=PLANE('',#994);
#996=CARTESIAN_POINT('',(34.,-18.1901536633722,0.));
#997=DIRECTION('',(0.,0.,1.));
#998=DIRECTION('',(1.,0.,0.));
#999=AXIS2_PLACEMENT_3D('',#996,#997,#998);
#1000=CIRCLE('',#999,2.2);
#1001=CARTESIAN_POINT('',(36.2,-18.1901536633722,0.));
#1002=VERTEX_POINT('',#1001);
#1003=EDGE_CURVE('E598',#1002,#1002,#1000,.T.);
#1004=ORIENTED_EDGE('',*,*,#1003,.F.);
#1005=EDGE_LOOP('',(#1004));
#1006=FACE_BOUND('',#1005,.T.);
#1007=CARTESIAN_POINT('',(9.,18.1901536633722,0.));
#1008=DIRECTION('',(0.,0.,1.));
#1009=DIRECTION('',(1.,0.,0.));
#1010=AXIS2_PLACEMENT_3D('',#1007,#1008,#1009);
#1011=CIRCLE('',#1010,2.2);
#1012=CARTESIAN_POINT('',(11.2,18.1901536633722,0.));
#1013=VERTEX_POINT('',#1012);
#1014=EDGE_CURVE('E603',#1013,#1013,#1011,.T.);
#1015=ORIENTED_EDGE('',*,*,#1014,.F.);
#1016=EDGE_LOOP('',(#1015));
#1017=FACE_BOUND('',#1016,.T.);
#1018=CARTESIAN_POINT('',(34.,18.1901536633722,0.));
#1019=DIRECTION('',(0.,0.,1.));
#1020=DIRECTION('',(1.,0.,0.));
#1021=AXIS2_PLACEMENT_3D('',#1018,#1019,#1020);
#1022=CIRCLE('',#1021,2.2);
#1023=CARTESIAN_POINT('',(36.2,18.1901536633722,0.));
#1024=VERTEX_POINT('',#1023);
#1025=EDGE_CURVE('E607',#1024,#1024,#1022,.T.);
#1026=ORIENTED_EDGE('',*,*,#1025,.F.);
#1027=EDGE_LOOP('',(#1026));
#1028=FACE_BOUND('',#1027,.T.);
#1029=CARTESIAN_POINT('',(9.,-18.1901536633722,0.));
#1030=DIRECTION('',(0.,0.,1.));
#1031=DIRECTION('',(1.,0.,0.));
#1032=AXIS2_PLACEMENT_3D('',#1029,#1030,#1031);
#1033=CIRCLE('',#1032,2.2);
#1034=CARTESIAN_POINT('',(11.2,-18.1901536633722,0.));
#1035=VERTEX_POINT('',#1034);
#1036=EDGE_CURVE('E612',#1035,#1035,#1033,.T.);
#1037=ORIENTED_EDGE('',*,*,#1036,.F.);
#1038=EDGE_LOOP('',(#1037));
#1039=FACE_BOUND('',#1038,.T.);
#1040=ORIENTED_EDGE('',*,*,#800,.F.);
#1041=CARTESIAN_POINT('',(45.,-18.6901536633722,0.));
#1042=DIRECTION('',(0.,0.,-1.));
#1043=DIRECTION('',(0.,1.,0.));
#1044=AXIS2_PLACEMENT_3D('',#1041,#1042,#1043);
#1045=CIRCLE('',#1044,5.);
#1046=CARTESIAN_POINT('',(50.,-18.6901536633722,0.));
#1047=VERTEX_POINT('',#1046);
#1048=EDGE_CURVE('E513',#791,#1047,#1045,.F.);
#1049=ORIENTED_EDGE('',*,*,#1048,.T.);
#1050=DIRECTION('',(0.,-1.,0.));
#1051=VECTOR('',#1050,1.);
#1052=CARTESIAN_POINT('',(50.,-12.6901536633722,0.));
#1053=LINE('',#1052,#1051);
#1054=CARTESIAN_POINT('',(50.,18.6901536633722,0.));
#1055=VERTEX_POINT('',#1054);
#1056=EDGE_CURVE('E187',#1055,#1047,#1053,.T.);
#1057=ORIENTED_EDGE('',*,*,#1056,.F.);
#1058=CARTESIAN_POINT('',(45.,18.6901536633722,0.));
#1059=DIRECTION('',(0.,0.,-1.));
#1060=DIRECTION('',(0.,1.,0.));
#1061=AXIS2_PLACEMENT_3D('',#1058,#1059,#1060);
#1062=CIRCLE('',#1061,5.);
#1063=EDGE_CURVE('E523',#1055,#970,#1062,.F.);
#1064=ORIENTED_EDGE('',*,*,#1063,.T.);
#1065=ORIENTED_EDGE('',*,*,#973,.T.);
#1066=DIRECTION('',(0.,-1.,0.));
#1067=VECTOR('',#1066,1.);
#1068=CARTESIAN_POINT('',(0.,12.6901536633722,0.));
#1069=LINE('',#1068,#1067);
#1070=EDGE_CURVE('E201',#972,#758,#1069,.T.);
#1071=ORIENTED_EDGE('',*,*,#1070,.T.);
#1072=ORIENTED_EDGE('',*,*,#759,.F.);
#1073=CARTESIAN_POINT('',(43.,12.6901536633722,0.));
#1074=CARTESIAN_POINT('',(43.0281185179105,12.6901534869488,0.));
#1075=CARTESIAN_POINT('',(43.056223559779,12.6889660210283,0.));
#1076=CARTESIAN_POINT('',(43.1122324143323,12.6842288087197,0.));
#1077=CARTESIAN_POINT('',(43.14013623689,12.6806791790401,0.));
#1078=CARTESIAN_POINT('',(43.2231960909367,12.6665210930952,0.));
#1079=CARTESIAN_POINT('',(43.2777955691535,12.6524033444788,0.));
#1080=CARTESIAN_POINT('',(43.3838475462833,12.6152028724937,0.));
#1081=CARTESIAN_POINT('',(43.4352985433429,12.5921159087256,0.));
#1082=CARTESIAN_POINT('',(43.5335947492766,12.5376368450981,0.));
#1083=CARTESIAN_POINT('',(43.5804407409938,12.5062461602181,0.));
#1084=CARTESIAN_POINT('',(43.6682146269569,12.436040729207,0.));
#1085=CARTESIAN_POINT('',(43.7091406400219,12.3972236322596,0.));
#1086=CARTESIAN_POINT('',(43.7839094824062,12.3132649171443,0.));
#1087=CARTESIAN_POINT('',(43.8177509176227,12.2681220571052,0.));
#1088=CARTESIAN_POINT('',(43.8774110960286,12.1727610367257,0.));
#1089=CARTESIAN_POINT('',(43.9032223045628,12.1225381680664,0.));
#1090=CARTESIAN_POINT('',(43.9460411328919,12.0184839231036,0.));
#1091=CARTESIAN_POINT('',(43.9630537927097,11.9646546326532,0.));
#1092=CARTESIAN_POINT('',(43.9835962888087,11.8736358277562,0.));
#1093=CARTESIAN_POINT('',(43.9897440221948,11.8370156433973,0.));
#1094=CARTESIAN_POINT('',(43.9979453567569,11.7633724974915,0.));
#1095=CARTESIAN_POINT('',(44.0000047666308,11.7263501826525,0.));
#1096=CARTESIAN_POINT('',(44.,11.689311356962,0.));
#1097=B_SPLINE_CURVE_WITH_KNOTS('',3,(#1073,#1074,#1075,#1076,#1077,#1078,#1079,#1080,#1081,
#1082,#1083,#1084,#1085,#1086,#1087,#1088,#1089,#1090,#1091,#1092,#1093,#1094,#1095,#1096),
.UNSPECIFIED.,.F.,.F.,(4,2,2,2,2,2,2,2,2,2,2,4),(0.,0.084303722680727,0.168603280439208,
0.336920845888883,0.505318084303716,0.673686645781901,0.842108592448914,1.01056365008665,
1.17917629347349,1.34769224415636,1.45887744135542,1.56990455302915),.UNSPECIFIED.);
#1098=CARTESIAN_POINT('',(44.,11.689311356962,0.));
#1099=VERTEX_POINT('',#1098);
#1100=EDGE_CURVE('E228',#750,#1099,#1097,.T.);
#1101=ORIENTED_EDGE('',*,*,#1100,.T.);
#1102=DIRECTION('',(0.,-1.,0.));
#1103=VECTOR('',#1102,1.);
#1104=CARTESIAN_POINT('',(44.,-12.6901536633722,0.));
#1105=LINE('',#1104,#1103);
#1106=CARTESIAN_POINT('',(44.,-11.689311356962,0.));
#1107=VERTEX_POINT('',#1106);
#1108=EDGE_CURVE('E179',#1099,#1107,#1105,.T.);
#1109=ORIENTED_EDGE('',*,*,#1108,.T.);
#1110=CARTESIAN_POINT('',(44.,-11.689311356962,0.));
#1111=CARTESIAN_POINT('',(43.9999997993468,-11.71748787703,0.));
#1112=CARTESIAN_POINT('',(43.998810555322,-11.7456509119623,0.));
#1113=CARTESIAN_POINT('',(43.9940659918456,-11.801775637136,0.));
#1114=CARTESIAN_POINT('',(43.9905107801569,-11.8297373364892,0.));
#1115=CARTESIAN_POINT('',(43.9763293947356,-11.9129726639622,0.));
#1116=CARTESIAN_POINT('',(43.962187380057,-11.9676890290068,0.));
#1117=CARTESIAN_POINT('',(43.9249172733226,-12.0739697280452,0.));
#1118=CARTESIAN_POINT('',(43.9017847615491,-12.1255324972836,0.));
#1119=CARTESIAN_POINT('',(43.8471900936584,-12.2240382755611,0.));
#1120=CARTESIAN_POINT('',(43.815729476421,-12.270982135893,0.));
#1121=CARTESIAN_POINT('',(43.7453851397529,-12.3588941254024,0.));
#1122=CARTESIAN_POINT('',(43.7065048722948,-12.3998650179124,0.));
#1123=CARTESIAN_POINT('',(43.6224034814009,-12.4747002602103,0.));
#1124=CARTESIAN_POINT('',(43.5771811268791,-12.5085632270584,0.));
#1125=CARTESIAN_POINT('',(43.4817218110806,-12.5681863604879,0.));
#1126=CARTESIAN_POINT('',(43.4314879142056,-12.5939514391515,0.));
#1127=CARTESIAN_POINT('',(43.3274155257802,-12.6366622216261,0.));
#1128=CARTESIAN_POINT('',(43.2735792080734,-12.6536131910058,0.));
#1129=CARTESIAN_POINT('',(43.1828408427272,-12.6739730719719,0.));
#1130=CARTESIAN_POINT('',(43.1465124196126,-12.6800371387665,0.));
#1131=CARTESIAN_POINT('',(43.073461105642,-12.6881268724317,0.));
#1132=CARTESIAN_POINT('',(43.0367388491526,-12.6901582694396,0.));
#1133=CARTESIAN_POINT('',(43.,-12.6901536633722,0.));
#1134=B_SPLINE_CURVE_WITH_KNOTS('',3,(#1110,#1111,#1112,#1113,#1114,#1115,#1116,#1117,#1118,
#1119,#1120,#1121,#1122,#1123,#1124,#1125,#1126,#1127,#1128,#1129,#1130,#1131,#1132,#1133),
.UNSPECIFIED.,.F.,.F.,(4,2,2,2,2,2,2,2,2,2,2,4),(0.,0.0844776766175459,0.168951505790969,
0.337625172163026,0.506381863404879,0.675107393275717,0.843754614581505,1.01243461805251,
1.1810121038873,1.34948876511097,1.45977370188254,1.56990181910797),.UNSPECIFIED.);
#1135=EDGE_CURVE('E160',#1107,#739,#1134,.T.);
#1136=ORIENTED_EDGE('',*,*,#1135,.T.);
#1137=ORIENTED_EDGE('',*,*,#742,.T.);
#1138=DIRECTION('',(0.,-1.,0.));
#1139=VECTOR('',#1138,1.);
#1140=CARTESIAN_POINT('',(0.,-12.6901536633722,0.));
#1141=LINE('',#1140,#1139);
#1142=EDGE_CURVE('E152',#741,#799,#1141,.T.);
#1143=ORIENTED_EDGE('',*,*,#1142,.T.);
#1144=EDGE_LOOP('',(#1040,#1049,#1057,#1064,#1065,#1071,#1072,#1101,#1109,#1136,#1137,#1143));
#1145=FACE_BOUND('',#1144,.T.);
#1146=ADVANCED_FACE('F154',(#1006,#1017,#1028,#1039,#1145),#995,.F.);
#1147=CARTESIAN_POINT('',(50.,0.,0.500000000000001));
#1148=DIRECTION('',(1.,0.,0.));
#1149=DIRECTION('',(0.,0.,-1.));
#1150=AXIS2_PLACEMENT_3D('',#1147,#1148,#1149);
#1151=PLANE('',#1150);
#1152=ORIENTED_EDGE('',*,*,#1056,.T.);
#1153=DIRECTION('',(0.,0.,-1.));
#1154=VECTOR('',#1153,1.);
#1155=CARTESIAN_POINT('',(50.,-18.6901536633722,-8.));
#1156=LINE('',#1155,#1154);
#1157=CARTESIAN_POINT('',(50.,-18.6901536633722,-4.92775273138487));
#1158=VERTEX_POINT('',#1157);
#1159=EDGE_CURVE('E558',#1047,#1158,#1156,.T.);
#1160=ORIENTED_EDGE('',*,*,#1159,.T.);
#1161=CARTESIAN_POINT('',(50.,-28.2874518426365,-20.2));
#1162=DIRECTION('',(1.,0.,0.));
#1163=DIRECTION('',(0.,0.,-1.));
#1164=AXIS2_PLACEMENT_3D('',#1161,#1162,#1163);
#1165=CIRCLE('',#1164,18.0374518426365);
#1166=CARTESIAN_POINT('',(50.,-10.9568526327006,-15.2));
#1167=VERTEX_POINT('',#1166);
#1168=EDGE_CURVE('E569',#1158,#1167,#1165,.F.);
#1169=ORIENTED_EDGE('',*,*,#1168,.T.);
#1170=DIRECTION('',(0.,1.,0.));
#1171=VECTOR('',#1170,1.);
#1172=CARTESIAN_POINT('',(50.,15.25,-15.2));
#1173=LINE('',#1172,#1171);
#1174=CARTESIAN_POINT('',(50.,10.9568526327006,-15.2));
#1175=VERTEX_POINT('',#1174);
#1176=EDGE_CURVE('E568',#1167,#1175,#1173,.T.);
#1177=ORIENTED_EDGE('',*,*,#1176,.T.);
#1178=CARTESIAN_POINT('',(50.,28.2874518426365,-20.2));
#1179=DIRECTION('',(1.,0.,0.));
#1180=DIRECTION('',(0.,0.,-1.));
#1181=AXIS2_PLACEMENT_3D('',#1178,#1179,#1180);
#1182=CIRCLE('',#1181,18.0374518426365);
#1183=CARTESIAN_POINT('',(50.,18.6901536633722,-4.92775273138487));
#1184=VERTEX_POINT('',#1183);
#1185=EDGE_CURVE('E532',#1175,#1184,#1182,.F.);
#1186=ORIENTED_EDGE('',*,*,#1185,.T.);
#1187=DIRECTION('',(0.,0.,1.));
#1188=VECTOR('',#1187,1.);
#1189=CARTESIAN_POINT('',(50.,18.6901536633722,0.));
#1190=LINE('',#1189,#1188);
#1191=EDGE_CURVE('E561',#1184,#1055,#1190,.T.);
#1192=ORIENTED_EDGE('',*,*,#1191,.T.);
#1193=EDGE_LOOP('',(#1152,#1160,#1169,#1177,#1186,#1192));
#1194=FACE_BOUND('',#1193,.T.);
#1195=ADVANCED_FACE('F580',(#1194),#1151,.T.);
#1196=CARTESIAN_POINT('',(0.,0.,0.500000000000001));
#1197=DIRECTION('',(1.,0.,0.));
#1198=DIRECTION('',(0.,0.,-1.));
#1199=AXIS2_PLACEMENT_3D('',#1196,#1197,#1198);
#1200=PLANE('',#1199);
#1201=ORIENTED_EDGE('',*,*,#955,.F.);
#1202=CARTESIAN_POINT('',(0.,10.9568526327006,-15.2));
#1203=DIRECTION('',(1.,0.,0.));
#1204=DIRECTION('',(0.,0.,-1.));
#1205=AXIS2_PLACEMENT_3D('',#1202,#1203,#1204);
#1206=CIRCLE('',#1205,5.);
#1207=EDGE_CURVE('E274',#947,#884,#1206,.F.);
#1208=ORIENTED_EDGE('',*,*,#1207,.T.);
#1209=ORIENTED_EDGE('',*,*,#885,.F.);
#1210=CARTESIAN_POINT('',(0.,-10.9568526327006,-15.2));
#1211=DIRECTION('',(1.,0.,0.));
#1212=DIRECTION('',(0.,0.,-1.));
#1213=AXIS2_PLACEMENT_3D('',#1210,#1211,#1212);
#1214=CIRCLE('',#1213,5.);
#1215=EDGE_CURVE('E70',#882,#827,#1214,.F.);
#1216=ORIENTED_EDGE('',*,*,#1215,.T.);
#1217=ORIENTED_EDGE('',*,*,#845,.F.);
#1218=ORIENTED_EDGE('',*,*,#806,.F.);
#1219=ORIENTED_EDGE('',*,*,#1142,.F.);
#1220=ORIENTED_EDGE('',*,*,#766,.F.);
#1221=ORIENTED_EDGE('',*,*,#1070,.F.);
#1222=ORIENTED_EDGE('',*,*,#986,.F.);
#1223=EDGE_LOOP('',(#1201,#1208,#1209,#1216,#1217,#1218,#1219,#1220,#1221,#1222));
#1224=FACE_BOUND('',#1223,.T.);
#1225=ADVANCED_FACE('F166',(#1224),#1200,.F.);
#1226=CARTESIAN_POINT('',(44.,0.,0.500000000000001));
#1227=DIRECTION('',(1.,0.,0.));
#1228=DIRECTION('',(0.,0.,-1.));
#1229=AXIS2_PLACEMENT_3D('',#1226,#1227,#1228);
#1230=PLANE('',#1229);
#1231=ORIENTED_EDGE('',*,*,#1108,.F.);
#1232=CARTESIAN_POINT('',(44.,0.,0.500000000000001));
#1233=DIRECTION('',(1.,0.,0.));
#1234=DIRECTION('',(0.,0.,-1.));
#1235=AXIS2_PLACEMENT_3D('',#1232,#1233,#1234);
#1236=CIRCLE('',#1235,11.7);
#1237=EDGE_CURVE('E224',#1099,#1107,#1236,.F.);
#1238=ORIENTED_EDGE('',*,*,#1237,.T.);
#1239=EDGE_LOOP('',(#1231,#1238));
#1240=FACE_BOUND('',#1239,.T.);
#1241=ADVANCED_FACE('F248',(#1240),#1230,.F.);
#1242=CARTESIAN_POINT('',(43.,0.,0.500000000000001));
#1243=DIRECTION('',(1.,0.,0.));
#1244=DIRECTION('',(0.,0.,-1.));
#1245=AXIS2_PLACEMENT_3D('',#1242,#1243,#1244);
#1246=TOROIDAL_SURFACE('',#1245,11.7,1.);
#1247=ORIENTED_EDGE('',*,*,#1135,.F.);
#1248=ORIENTED_EDGE('',*,*,#1237,.F.);
#1249=ORIENTED_EDGE('',*,*,#1100,.F.);
#1250=ORIENTED_EDGE('',*,*,#751,.F.);
#1251=EDGE_LOOP('',(#1247,#1248,#1249,#1250));
#1252=FACE_BOUND('',#1251,.T.);
#1253=ADVANCED_FACE('F243',(#1252),#1246,.F.);
#1254=CARTESIAN_POINT('',(45.,18.6901536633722,0.500000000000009));
#1255=DIRECTION('',(0.,0.,-1.));
#1256=DIRECTION('',(0.,1.,0.));
#1257=AXIS2_PLACEMENT_3D('',#1254,#1255,#1256);
#1258=CYLINDRICAL_SURFACE('',#1257,5.);
#1259=ORIENTED_EDGE('',*,*,#1063,.F.);
#1260=ORIENTED_EDGE('',*,*,#1191,.F.);
#1261=CARTESIAN_POINT('',(45.,23.6901536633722,-8.));
#1262=CARTESIAN_POINT('',(45.1239443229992,23.6901790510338,-8.00002267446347));
#1263=CARTESIAN_POINT('',(45.2478746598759,23.6855461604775,-7.99681257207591));
#1264=CARTESIAN_POINT('',(45.4946695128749,23.6671544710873,-7.98409614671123));
#1265=CARTESIAN_POINT('',(45.6175345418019,23.6534003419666,-7.97459304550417));
#1266=CARTESIAN_POINT('',(45.8605879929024,23.6170613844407,-7.94953199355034));
#1267=CARTESIAN_POINT('',(45.9807877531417,23.5945278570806,-7.93400922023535));
#1268=CARTESIAN_POINT('',(46.2183818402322,23.5409654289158,-7.89720830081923));
#1269=CARTESIAN_POINT('',(46.3357759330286,23.5099358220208,-7.87592967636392));
#1270=CARTESIAN_POINT('',(46.5667612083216,23.439868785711,-7.82803751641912));
#1271=CARTESIAN_POINT('',(46.6803595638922,23.4008475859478,-7.80143479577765));
#1272=CARTESIAN_POINT('',(46.9033832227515,23.3152397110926,-7.74329460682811));
#1273=CARTESIAN_POINT('',(47.0128068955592,23.2686501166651,-7.71175523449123));
#1274=CARTESIAN_POINT('',(47.3341609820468,23.1181990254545,-7.61034830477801));
#1275=CARTESIAN_POINT('',(47.5390936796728,23.0036801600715,-7.53370912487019));
#1276=CARTESIAN_POINT('',(47.9412885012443,22.7411786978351,-7.3599430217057));
#1277=CARTESIAN_POINT('',(48.1368434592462,22.591339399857,-7.26171553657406));
#1278=CARTESIAN_POINT('',(48.5004024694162,22.2687384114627,-7.05295338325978));
#1279=CARTESIAN_POINT('',(48.6684013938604,22.095972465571,-6.94241643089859));
#1280=CARTESIAN_POINT('',(49.0013207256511,21.7012616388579,-6.69329560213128));
#1281=CARTESIAN_POINT('',(49.1610245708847,21.4759246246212,-6.55311322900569));
#1282=CARTESIAN_POINT('',(49.4400180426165,21.0055655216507,-6.26524288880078));
#1283=CARTESIAN_POINT('',(49.5592554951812,20.7605185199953,-6.11754551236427));
#1284=CARTESIAN_POINT('',(49.7700891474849,20.2204576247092,-5.79726890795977));
#1285=CARTESIAN_POINT('',(49.8553449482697,19.9232930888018,-5.62413769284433));
#1286=CARTESIAN_POINT('',(49.9698050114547,19.3188492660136,-5.27824457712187));
#1287=CARTESIAN_POINT('',(49.9991524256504,19.0115978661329,-5.10548286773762));
#1288=CARTESIAN_POINT('',(49.9999939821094,18.699121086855,-4.93270914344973));
#1289=CARTESIAN_POINT('',(50.0000000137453,18.6946374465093,-4.93023067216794));
#1290=CARTESIAN_POINT('',(50.,18.6901536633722,-4.92775273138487));
#1291=B_SPLINE_CURVE_WITH_KNOTS('',3,(#1261,#1262,#1263,#1264,#1265,#1266,#1267,#1268,#1269,
#1270,#1271,#1272,#1273,#1274,#1275,#1276,#1277,#1278,#1279,#1280,#1281,#1282,#1283,#1284,#1285,
#1286,#1287,#1288,#1289,#1290),.UNSPECIFIED.,.F.,.F.,(4,2,2,2,2,2,2,2,2,2,2,2,2,2,4),(0.,
0.371682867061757,0.743175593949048,1.11252935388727,1.48191381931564,1.85055543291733,
2.21933958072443,2.95716378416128,3.74992267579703,4.54282891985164,5.46837976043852,
6.39511943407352,7.45362238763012,8.50941141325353,8.52478061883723),.UNSPECIFIED.);
#1292=EDGE_CURVE('E299',#928,#1184,#1291,.T.);
#1293=ORIENTED_EDGE('',*,*,#1292,.F.);
#1294=ORIENTED_EDGE('',*,*,#979,.F.);
#1295=EDGE_LOOP('',(#1259,#1260,#1293,#1294));
#1296=FACE_BOUND('',#1295,.T.);
#1297=ADVANCED_FACE('F247',(#1296),#1258,.T.);
#1298=CARTESIAN_POINT('',(45.,28.2874518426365,-20.2));
#1299=DIRECTION('',(1.,0.,0.));
#1300=DIRECTION('',(0.,0.,-1.));
#1301=AXIS2_PLACEMENT_3D('',#1298,#1299,#1300);
#1302=TOROIDAL_SURFACE('',#1301,18.0374518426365,5.);
#1303=ORIENTED_EDGE('',*,*,#1292,.T.);
#1304=ORIENTED_EDGE('',*,*,#1185,.F.);
#1305=CARTESIAN_POINT('',(45.,10.9568526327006,-15.2));
#1306=DIRECTION('',(0.,-0.277201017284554,-0.960811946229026));
#1307=DIRECTION('',(0.,0.960811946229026,-0.277201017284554));
#1308=AXIS2_PLACEMENT_3D('',#1305,#1306,#1307);
#1309=CIRCLE('',#1308,5.);
#1310=EDGE_CURVE('E294',#939,#1175,#1309,.T.);
#1311=ORIENTED_EDGE('',*,*,#1310,.F.);
#1312=ORIENTED_EDGE('',*,*,#940,.F.);
#1313=EDGE_LOOP('',(#1303,#1304,#1311,#1312));
#1314=FACE_BOUND('',#1313,.T.);
#1315=ADVANCED_FACE('F317',(#1314),#1302,.T.);
#1316=CARTESIAN_POINT('',(50.,10.9568526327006,-15.2));
#1317=DIRECTION('',(-1.,0.,0.));
#1318=DIRECTION('',(0.,0.,1.));
#1319=AXIS2_PLACEMENT_3D('',#1316,#1317,#1318);
#1320=CYLINDRICAL_SURFACE('',#1319,5.);
#1321=ORIENTED_EDGE('',*,*,#1207,.F.);
#1322=ORIENTED_EDGE('',*,*,#948,.F.);
#1323=CARTESIAN_POINT('',(45.,10.9568526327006,-15.2));
#1324=DIRECTION('',(1.,0.,0.));
#1325=DIRECTION('',(0.,0.,-1.));
#1326=AXIS2_PLACEMENT_3D('',#1323,#1324,#1325);
#1327=CIRCLE('',#1326,5.);
#1328=EDGE_CURVE('E293',#892,#939,#1327,.T.);
#1329=ORIENTED_EDGE('',*,*,#1328,.F.);
#1330=ORIENTED_EDGE('',*,*,#893,.F.);
#1331=EDGE_LOOP('',(#1321,#1322,#1329,#1330));
#1332=FACE_BOUND('',#1331,.T.);
#1333=ADVANCED_FACE('F486',(#1332),#1320,.T.);
#1334=CARTESIAN_POINT('',(45.,10.9568526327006,-15.2));
#1335=DIRECTION('',(1.,0.,0.));
#1336=DIRECTION('',(0.,0.,-1.));
#1337=AXIS2_PLACEMENT_3D('',#1334,#1335,#1336);
#1338=SPHERICAL_SURFACE('',#1337,5.);
#1339=ORIENTED_EDGE('',*,*,#1328,.T.);
#1340=ORIENTED_EDGE('',*,*,#1310,.T.);
#1341=CARTESIAN_POINT('',(45.,10.9568526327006,-15.2));
#1342=DIRECTION('',(0.,1.,0.));
#1343=DIRECTION('',(0.,0.,1.));
#1344=AXIS2_PLACEMENT_3D('',#1341,#1342,#1343);
#1345=CIRCLE('',#1344,5.);
#1346=EDGE_CURVE('E290',#892,#1175,#1345,.F.);
#1347=ORIENTED_EDGE('',*,*,#1346,.F.);
#1348=EDGE_LOOP('',(#1339,#1340,#1347));
#1349=FACE_BOUND('',#1348,.T.);
#1350=ADVANCED_FACE('F531',(#1349),#1338,.T.);
#1351=CARTESIAN_POINT('',(45.,0.,-15.2));
#1352=DIRECTION('',(0.,-1.,0.));
#1353=DIRECTION('',(0.,0.,-1.));
#1354=AXIS2_PLACEMENT_3D('',#1351,#1352,#1353);
#1355=CYLINDRICAL_SURFACE('',#1354,5.);
#1356=ORIENTED_EDGE('',*,*,#1346,.T.);
#1357=ORIENTED_EDGE('',*,*,#1176,.F.);
#1358=CARTESIAN_POINT('',(45.,-10.9568526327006,-15.2));
#1359=DIRECTION('',(0.,-1.,0.));
#1360=DIRECTION('',(1.,0.,0.));
#1361=AXIS2_PLACEMENT_3D('',#1358,#1359,#1360);
#1362=CIRCLE('',#1361,5.);
#1363=EDGE_CURVE('E282',#900,#1167,#1362,.T.);
#1364=ORIENTED_EDGE('',*,*,#1363,.F.);
#1365=ORIENTED_EDGE('',*,*,#901,.F.);
#1366=EDGE_LOOP('',(#1356,#1357,#1364,#1365));
#1367=FACE_BOUND('',#1366,.T.);
#1368=ADVANCED_FACE('F540',(#1367),#1355,.T.);
#1369=CARTESIAN_POINT('',(50.,-10.9568526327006,-15.2));
#1370=DIRECTION('',(-1.,0.,0.));
#1371=DIRECTION('',(0.,0.,1.));
#1372=AXIS2_PLACEMENT_3D('',#1369,#1370,#1371);
#1373=CYLINDRICAL_SURFACE('',#1372,5.);
#1374=ORIENTED_EDGE('',*,*,#1215,.F.);
#1375=ORIENTED_EDGE('',*,*,#907,.F.);
#1376=CARTESIAN_POINT('',(45.,-10.9568526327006,-15.2));
#1377=DIRECTION('',(1.,0.,0.));
#1378=DIRECTION('',(0.,0.,-1.));
#1379=AXIS2_PLACEMENT_3D('',#1376,#1377,#1378);
#1380=CIRCLE('',#1379,5.);
#1381=EDGE_CURVE('E278',#829,#900,#1380,.T.);
#1382=ORIENTED_EDGE('',*,*,#1381,.F.);
#1383=ORIENTED_EDGE('',*,*,#830,.F.);
#1384=EDGE_LOOP('',(#1374,#1375,#1382,#1383));
#1385=FACE_BOUND('',#1384,.T.);
#1386=ADVANCED_FACE('F537',(#1385),#1373,.T.);
#1387=CARTESIAN_POINT('',(45.,-10.9568526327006,-15.2));
#1388=DIRECTION('',(1.,0.,0.));
#1389=DIRECTION('',(0.,0.,-1.));
#1390=AXIS2_PLACEMENT_3D('',#1387,#1388,#1389);
#1391=SPHERICAL_SURFACE('',#1390,5.);
#1392=ORIENTED_EDGE('',*,*,#1381,.T.);
#1393=ORIENTED_EDGE('',*,*,#1363,.T.);
#1394=CARTESIAN_POINT('',(45.,-10.9568526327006,-15.2));
#1395=DIRECTION('',(0.,0.277201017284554,-0.960811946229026));
#1396=DIRECTION('',(0.,0.960811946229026,0.277201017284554));
#1397=AXIS2_PLACEMENT_3D('',#1394,#1395,#1396);
#1398=CIRCLE('',#1397,5.);
#1399=EDGE_CURVE('E275',#829,#1167,#1398,.F.);
#1400=ORIENTED_EDGE('',*,*,#1399,.F.);
#1401=EDGE_LOOP('',(#1392,#1393,#1400));
#1402=FACE_BOUND('',#1401,.T.);
#1403=ADVANCED_FACE('F545',(#1402),#1391,.T.);
#1404=CARTESIAN_POINT('',(45.,-28.2874518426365,-20.2));
#1405=DIRECTION('',(1.,0.,0.));
#1406=DIRECTION('',(0.,0.,-1.));
#1407=AXIS2_PLACEMENT_3D('',#1404,#1405,#1406);
#1408=TOROIDAL_SURFACE('',#1407,18.0374518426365,5.);
#1409=ORIENTED_EDGE('',*,*,#1399,.T.);
#1410=ORIENTED_EDGE('',*,*,#1168,.F.);
#1411=CARTESIAN_POINT('',(45.,-23.6901536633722,-8.));
#1412=CARTESIAN_POINT('',(45.1239443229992,-23.6901790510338,-8.00002267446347));
#1413=CARTESIAN_POINT('',(45.2478746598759,-23.6855461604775,-7.99681257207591));
#1414=CARTESIAN_POINT('',(45.4946695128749,-23.6671544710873,-7.98409614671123));
#1415=CARTESIAN_POINT('',(45.6175345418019,-23.6534003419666,-7.97459304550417));
#1416=CARTESIAN_POINT('',(45.8605879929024,-23.6170613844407,-7.94953199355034));
#1417=CARTESIAN_POINT('',(45.9807877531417,-23.5945278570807,-7.93400922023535));
#1418=CARTESIAN_POINT('',(46.2183818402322,-23.5409654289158,-7.89720830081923));
#1419=CARTESIAN_POINT('',(46.3357759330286,-23.5099358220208,-7.87592967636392));
#1420=CARTESIAN_POINT('',(46.5667612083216,-23.439868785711,-7.82803751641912));
#1421=CARTESIAN_POINT('',(46.6803595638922,-23.4008475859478,-7.80143479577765));
#1422=CARTESIAN_POINT('',(46.9033832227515,-23.3152397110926,-7.74329460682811));
#1423=CARTESIAN_POINT('',(47.0128068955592,-23.2686501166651,-7.71175523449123));
#1424=CARTESIAN_POINT('',(47.3341609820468,-23.1181990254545,-7.61034830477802));
#1425=CARTESIAN_POINT('',(47.5390936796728,-23.0036801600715,-7.53370912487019));
#1426=CARTESIAN_POINT('',(47.9412885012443,-22.7411786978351,-7.3599430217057));
#1427=CARTESIAN_POINT('',(48.1368434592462,-22.591339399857,-7.26171553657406));
#1428=CARTESIAN_POINT('',(48.5004024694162,-22.2687384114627,-7.05295338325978));
#1429=CARTESIAN_POINT('',(48.6684013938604,-22.095972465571,-6.94241643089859));
#1430=CARTESIAN_POINT('',(49.0013207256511,-21.7012616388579,-6.69329560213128));
#1431=CARTESIAN_POINT('',(49.1610245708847,-21.4759246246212,-6.55311322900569));
#1432=CARTESIAN_POINT('',(49.4400180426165,-21.0055655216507,-6.26524288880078));
#1433=CARTESIAN_POINT('',(49.5592554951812,-20.7605185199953,-6.11754551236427));
#1434=CARTESIAN_POINT('',(49.7700891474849,-20.2204576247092,-5.79726890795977));
#1435=CARTESIAN_POINT('',(49.8553449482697,-19.9232930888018,-5.62413769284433));
#1436=CARTESIAN_POINT('',(49.9698050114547,-19.3188492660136,-5.27824457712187));
#1437=CARTESIAN_POINT('',(49.9991524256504,-19.0115978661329,-5.10548286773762));
#1438=CARTESIAN_POINT('',(49.9999939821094,-18.699121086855,-4.93270914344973));
#1439=CARTESIAN_POINT('',(50.0000000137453,-18.6946374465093,-4.93023067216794));
#1440=CARTESIAN_POINT('',(50.,-18.6901536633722,-4.92775273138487));
#1441=B_SPLINE_CURVE_WITH_KNOTS('',3,(#1411,#1412,#1413,#1414,#1415,#1416,#1417,#1418,#1419,
#1420,#1421,#1422,#1423,#1424,#1425,#1426,#1427,#1428,#1429,#1430,#1431,#1432,#1433,#1434,#1435,
#1436,#1437,#1438,#1439,#1440),.UNSPECIFIED.,.F.,.F.,(4,2,2,2,2,2,2,2,2,2,2,2,2,2,4),(0.,
0.371682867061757,0.743175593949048,1.11252935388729,1.48191381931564,1.85055543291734,
2.21933958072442,2.95716378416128,3.74992267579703,4.54282891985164,5.46837976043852,
6.39511943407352,7.45362238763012,8.50941141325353,8.52478061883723),.UNSPECIFIED.);
#1442=EDGE_CURVE('E265',#781,#1158,#1441,.T.);
#1443=ORIENTED_EDGE('',*,*,#1442,.F.);
#1444=ORIENTED_EDGE('',*,*,#837,.F.);
#1445=EDGE_LOOP('',(#1409,#1410,#1443,#1444));
#1446=FACE_BOUND('',#1445,.T.);
#1447=ADVANCED_FACE('F258',(#1446),#1408,.T.);
#1448=CARTESIAN_POINT('',(45.,-18.6901536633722,0.500000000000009));
#1449=DIRECTION('',(0.,0.,1.));
#1450=DIRECTION('',(0.,-1.,0.));
#1451=AXIS2_PLACEMENT_3D('',#1448,#1449,#1450);
#1452=CYLINDRICAL_SURFACE('',#1451,5.);
#1453=ORIENTED_EDGE('',*,*,#1048,.F.);
#1454=ORIENTED_EDGE('',*,*,#792,.F.);
#1455=ORIENTED_EDGE('',*,*,#1442,.T.);
#1456=ORIENTED_EDGE('',*,*,#1159,.F.);
#1457=EDGE_LOOP('',(#1453,#1454,#1455,#1456));
#1458=FACE_BOUND('',#1457,.T.);
#1459=ADVANCED_FACE('F254',(#1458),#1452,.T.);
#1460=CARTESIAN_POINT('',(34.,0.,-14.2));
#1461=DIRECTION('',(0.,0.,-1.));
#1462=DIRECTION('',(-1.,0.,0.));
#1463=AXIS2_PLACEMENT_3D('',#1460,#1461,#1462);
#1464=CYLINDRICAL_SURFACE('',#1463,6.);
#1465=CARTESIAN_POINT('',(34.,0.,-15.2));
#1466=DIRECTION('',(0.,0.,-1.));
#1467=DIRECTION('',(-1.,0.,0.));
#1468=AXIS2_PLACEMENT_3D('',#1465,#1466,#1467);
#1469=CIRCLE('',#1468,6.);
#1470=CARTESIAN_POINT('',(28.,0.,-15.2));
#1471=VERTEX_POINT('',#1470);
#1472=EDGE_CURVE('E11',#1471,#1471,#1469,.F.);
#1473=ORIENTED_EDGE('',*,*,#1472,.T.);
#1474=EDGE_LOOP('',(#1473));
#1475=FACE_BOUND('',#1474,.T.);
#1476=ORIENTED_EDGE('',*,*,#873,.T.);
#1477=EDGE_LOOP('',(#1476));
#1478=FACE_BOUND('',#1477,.T.);
#1479=ADVANCED_FACE('F260',(#1475,#1478),#1464,.F.);
#1480=CARTESIAN_POINT('',(34.,0.,-14.2));
#1481=DIRECTION('',(0.,0.,-1.));
#1482=DIRECTION('',(-1.,0.,0.));
#1483=AXIS2_PLACEMENT_3D('',#1480,#1481,#1482);
#1484=PLANE('',#1483);
#1485=CARTESIAN_POINT('',(34.,0.,-14.2));
#1486=DIRECTION('',(0.,0.,-1.));
#1487=DIRECTION('',(-1.,0.,0.));
#1488=AXIS2_PLACEMENT_3D('',#1485,#1486,#1487);
#1489=CIRCLE('',#1488,5.);
#1490=CARTESIAN_POINT('',(29.,0.,-14.2));
#1491=VERTEX_POINT('',#1490);
#1492=EDGE_CURVE('E53',#1491,#1491,#1489,.T.);
#1493=ORIENTED_EDGE('',*,*,#1492,.T.);
#1494=EDGE_LOOP('',(#1493));
#1495=FACE_BOUND('',#1494,.T.);
#1496=CARTESIAN_POINT('',(34.,0.,-14.2));
#1497=DIRECTION('',(0.,0.,-1.));
#1498=DIRECTION('',(-1.,0.,0.));
#1499=AXIS2_PLACEMENT_3D('',#1496,#1497,#1498);
#1500=CIRCLE('',#1499,2.1);
#1501=CARTESIAN_POINT('',(31.9,0.,-14.2));
#1502=VERTEX_POINT('',#1501);
#1503=EDGE_CURVE('E447',#1502,#1502,#1500,.T.);
#1504=ORIENTED_EDGE('',*,*,#1503,.F.);
#1505=EDGE_LOOP('',(#1504));
#1506=FACE_BOUND('',#1505,.T.);
#1507=ADVANCED_FACE('F400',(#1495,#1506),#1484,.T.);
#1508=CARTESIAN_POINT('',(9.,0.,-14.2));
#1509=DIRECTION('',(0.,0.,-1.));
#1510=DIRECTION('',(-1.,0.,0.));
#1511=AXIS2_PLACEMENT_3D('',#1508,#1509,#1510);
#1512=CYLINDRICAL_SURFACE('',#1511,6.);
#1513=CARTESIAN_POINT('',(9.,0.,-15.2));
#1514=DIRECTION('',(0.,0.,-1.));
#1515=DIRECTION('',(-1.,0.,0.));
#1516=AXIS2_PLACEMENT_3D('',#1513,#1514,#1515);
#1517=CIRCLE('',#1516,6.);
#1518=CARTESIAN_POINT('',(3.,0.,-15.2));
#1519=VERTEX_POINT('',#1518);
#1520=EDGE_CURVE('E454',#1519,#1519,#1517,.F.);
#1521=ORIENTED_EDGE('',*,*,#1520,.T.);
#1522=EDGE_LOOP('',(#1521));
#1523=FACE_BOUND('',#1522,.T.);
#1524=ORIENTED_EDGE('',*,*,#862,.T.);
#1525=EDGE_LOOP('',(#1524));
#1526=FACE_BOUND('',#1525,.T.);
#1527=ADVANCED_FACE('F398',(#1523,#1526),#1512,.F.);
#1528=CARTESIAN_POINT('',(9.,0.,-14.2));
#1529=DIRECTION('',(0.,0.,-1.));
#1530=DIRECTION('',(-1.,0.,0.));
#1531=AXIS2_PLACEMENT_3D('',#1528,#1529,#1530);
#1532=PLANE('',#1531);
#1533=CARTESIAN_POINT('',(9.,0.,-14.2));
#1534=DIRECTION('',(0.,0.,-1.));
#1535=DIRECTION('',(-1.,0.,0.));
#1536=AXIS2_PLACEMENT_3D('',#1533,#1534,#1535);
#1537=CIRCLE('',#1536,5.);
#1538=CARTESIAN_POINT('',(4.,0.,-14.2));
#1539=VERTEX_POINT('',#1538);
#1540=EDGE_CURVE('E450',#1539,#1539,#1537,.T.);
#1541=ORIENTED_EDGE('',*,*,#1540,.T.);
#1542=EDGE_LOOP('',(#1541));
#1543=FACE_BOUND('',#1542,.T.);
#1544=CARTESIAN_POINT('',(9.,0.,-14.2));
#1545=DIRECTION('',(0.,0.,-1.));
#1546=DIRECTION('',(-1.,0.,0.));
#1547=AXIS2_PLACEMENT_3D('',#1544,#1545,#1546);
#1548=CIRCLE('',#1547,2.1);
#1549=CARTESIAN_POINT('',(6.9,0.,-14.2));
#1550=VERTEX_POINT('',#1549);
#1551=EDGE_CURVE('E465',#1550,#1550,#1548,.T.);
#1552=ORIENTED_EDGE('',*,*,#1551,.F.);
#1553=EDGE_LOOP('',(#1552));
#1554=FACE_BOUND('',#1553,.T.);
#1555=ADVANCED_FACE('F406',(#1543,#1554),#1532,.T.);
#1556=CARTESIAN_POINT('',(34.,0.,0.));
#1557=DIRECTION('',(0.,0.,-1.));
#1558=DIRECTION('',(-1.,0.,0.));
#1559=AXIS2_PLACEMENT_3D('',#1556,#1557,#1558);
#1560=CYLINDRICAL_SURFACE('',#1559,2.1);
#1561=ORIENTED_EDGE('',*,*,#1503,.T.);
#1562=EDGE_LOOP('',(#1561));
#1563=FACE_BOUND('',#1562,.T.);
#1564=ORIENTED_EDGE('',*,*,#730,.F.);
#1565=EDGE_LOOP('',(#1564));
#1566=FACE_BOUND('',#1565,.T.);
#1567=ADVANCED_FACE('F408',(#1563,#1566),#1560,.F.);
#1568=CARTESIAN_POINT('',(9.,0.,0.));
#1569=DIRECTION('',(0.,0.,-1.));
#1570=DIRECTION('',(-1.,0.,0.));
#1571=AXIS2_PLACEMENT_3D('',#1568,#1569,#1570);
#1572=CYLINDRICAL_SURFACE('',#1571,2.1);
#1573=ORIENTED_EDGE('',*,*,#1551,.T.);
#1574=EDGE_LOOP('',(#1573));
#1575=FACE_BOUND('',#1574,.T.);
#1576=ORIENTED_EDGE('',*,*,#645,.F.);
#1577=EDGE_LOOP('',(#1576));
#1578=FACE_BOUND('',#1577,.T.);
#1579=ADVANCED_FACE('F415',(#1575,#1578),#1572,.F.);
#1580=CARTESIAN_POINT('',(34.,18.1901536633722,-5.));
#1581=DIRECTION('',(0.,0.,1.));
#1582=DIRECTION('',(1.,0.,0.));
#1583=AXIS2_PLACEMENT_3D('',#1580,#1581,#1582);
#1584=PLANE('',#1583);
#1585=CARTESIAN_POINT('',(34.,18.1901536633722,-5.));
#1586=DIRECTION('',(0.,0.,1.));
#1587=DIRECTION('',(1.,0.,0.));
#1588=AXIS2_PLACEMENT_3D('',#1585,#1586,#1587);
#1589=CIRCLE('',#1588,2.2);
#1590=CARTESIAN_POINT('',(36.2,18.1901536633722,-5.));
#1591=VERTEX_POINT('',#1590);
#1592=EDGE_CURVE('E629',#1591,#1591,#1589,.T.);
#1593=ORIENTED_EDGE('',*,*,#1592,.T.);
#1594=EDGE_LOOP('',(#1593));
#1595=FACE_BOUND('',#1594,.T.);
#1596=ORIENTED_EDGE('',*,*,#554,.T.);
#1597=EDGE_LOOP('',(#1596));
#1598=FACE_BOUND('',#1597,.T.);
#1599=ADVANCED_FACE('F419',(#1595,#1598),#1584,.T.);
#1600=CARTESIAN_POINT('',(34.,18.1901536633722,-5.));
#1601=DIRECTION('',(0.,0.,1.));
#1602=DIRECTION('',(1.,0.,0.));
#1603=AXIS2_PLACEMENT_3D('',#1600,#1601,#1602);
#1604=CYLINDRICAL_SURFACE('',#1603,2.2);
#1605=ORIENTED_EDGE('',*,*,#1592,.F.);
#1606=EDGE_LOOP('',(#1605));
#1607=FACE_BOUND('',#1606,.T.);
#1608=ORIENTED_EDGE('',*,*,#1025,.T.);
#1609=EDGE_LOOP('',(#1608));
#1610=FACE_BOUND('',#1609,.T.);
#1611=ADVANCED_FACE('F636',(#1607,#1610),#1604,.F.);
#1612=CARTESIAN_POINT('',(9.,-18.1901536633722,-5.));
#1613=DIRECTION('',(0.,0.,1.));
#1614=DIRECTION('',(1.,0.,0.));
#1615=AXIS2_PLACEMENT_3D('',#1612,#1613,#1614);
#1616=PLANE('',#1615);
#1617=CARTESIAN_POINT('',(9.,-18.1901536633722,-5.));
#1618=DIRECTION('',(0.,0.,1.));
#1619=DIRECTION('',(1.,0.,0.));
#1620=AXIS2_PLACEMENT_3D('',#1617,#1618,#1619);
#1621=CIRCLE('',#1620,2.2);
#1622=CARTESIAN_POINT('',(11.2,-18.1901536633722,-5.));
#1623=VERTEX_POINT('',#1622);
#1624=EDGE_CURVE('E432',#1623,#1623,#1621,.T.);
#1625=ORIENTED_EDGE('',*,*,#1624,.T.);
#1626=EDGE_LOOP('',(#1625));
#1627=FACE_BOUND('',#1626,.T.);
#1628=ORIENTED_EDGE('',*,*,#418,.T.);
#1629=EDGE_LOOP('',(#1628));
#1630=FACE_BOUND('',#1629,.T.);
#1631=ADVANCED_FACE('F637',(#1627,#1630),#1616,.T.);
#1632=CARTESIAN_POINT('',(9.,-18.1901536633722,-5.));
#1633=DIRECTION('',(0.,0.,1.));
#1634=DIRECTION('',(1.,0.,0.));
#1635=AXIS2_PLACEMENT_3D('',#1632,#1633,#1634);
#1636=CYLINDRICAL_SURFACE('',#1635,2.2);
#1637=ORIENTED_EDGE('',*,*,#1624,.F.);
#1638=EDGE_LOOP('',(#1637));
#1639=FACE_BOUND('',#1638,.T.);
#1640=ORIENTED_EDGE('',*,*,#1036,.T.);
#1641=EDGE_LOOP('',(#1640));
#1642=FACE_BOUND('',#1641,.T.);
#1643=ADVANCED_FACE('F418',(#1639,#1642),#1636,.F.);
#1644=CARTESIAN_POINT('',(34.,-18.1901536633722,-5.));
#1645=DIRECTION('',(0.,0.,1.));
#1646=DIRECTION('',(1.,0.,0.));
#1647=AXIS2_PLACEMENT_3D('',#1644,#1645,#1646);
#1648=PLANE('',#1647);
#1649=CARTESIAN_POINT('',(34.,-18.1901536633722,-5.));
#1650=DIRECTION('',(0.,0.,1.));
#1651=DIRECTION('',(1.,0.,0.));
#1652=AXIS2_PLACEMENT_3D('',#1649,#1650,#1651);
#1653=CIRCLE('',#1652,2.2);
#1654=CARTESIAN_POINT('',(36.2,-18.1901536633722,-5.));
#1655=VERTEX_POINT('',#1654);
#1656=EDGE_CURVE('E616',#1655,#1655,#1653,.T.);
#1657=ORIENTED_EDGE('',*,*,#1656,.T.);
#1658=EDGE_LOOP('',(#1657));
#1659=FACE_BOUND('',#1658,.T.);
#1660=ORIENTED_EDGE('',*,*,#284,.T.);
#1661=EDGE_LOOP('',(#1660));
#1662=FACE_BOUND('',#1661,.T.);
#1663=ADVANCED_FACE('F654',(#1659,#1662),#1648,.T.);
#1664=CARTESIAN_POINT('',(34.,-18.1901536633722,-5.));
#1665=DIRECTION('',(0.,0.,1.));
#1666=DIRECTION('',(1.,0.,0.));
#1667=AXIS2_PLACEMENT_3D('',#1664,#1665,#1666);
#1668=CYLINDRICAL_SURFACE('',#1667,2.2);
#1669=ORIENTED_EDGE('',*,*,#1656,.F.);
#1670=EDGE_LOOP('',(#1669));
#1671=FACE_BOUND('',#1670,.T.);
#1672=ORIENTED_EDGE('',*,*,#1003,.T.);
#1673=EDGE_LOOP('',(#1672));
#1674=FACE_BOUND('',#1673,.T.);
#1675=ADVANCED_FACE('F648',(#1671,#1674),#1668,.F.);
#1676=CARTESIAN_POINT('',(9.,18.1901536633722,-5.));
#1677=DIRECTION('',(0.,0.,1.));
#1678=DIRECTION('',(1.,0.,0.));
#1679=AXIS2_PLACEMENT_3D('',#1676,#1677,#1678);
#1680=PLANE('',#1679);
#1681=CARTESIAN_POINT('',(9.,18.1901536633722,-5.));
#1682=DIRECTION('',(0.,0.,1.));
#1683=DIRECTION('',(1.,0.,0.));
#1684=AXIS2_PLACEMENT_3D('',#1681,#1682,#1683);
#1685=CIRCLE('',#1684,2.2);
#1686=CARTESIAN_POINT('',(11.2,18.1901536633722,-5.));
#1687=VERTEX_POINT('',#1686);
#1688=EDGE_CURVE('E623',#1687,#1687,#1685,.T.);
#1689=ORIENTED_EDGE('',*,*,#1688,.T.);
#1690=EDGE_LOOP('',(#1689));
#1691=FACE_BOUND('',#1690,.T.);
#1692=ORIENTED_EDGE('',*,*,#150,.T.);
#1693=EDGE_LOOP('',(#1692));
#1694=FACE_BOUND('',#1693,.T.);
#1695=ADVANCED_FACE('F335',(#1691,#1694),#1680,.T.);
#1696=CARTESIAN_POINT('',(9.,18.1901536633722,-5.));
#1697=DIRECTION('',(0.,0.,1.));
#1698=DIRECTION('',(1.,0.,0.));
#1699=AXIS2_PLACEMENT_3D('',#1696,#1697,#1698);
#1700=CYLINDRICAL_SURFACE('',#1699,2.2);
#1701=ORIENTED_EDGE('',*,*,#1688,.F.);
#1702=EDGE_LOOP('',(#1701));
#1703=FACE_BOUND('',#1702,.T.);
#1704=ORIENTED_EDGE('',*,*,#1014,.T.);
#1705=EDGE_LOOP('',(#1704));
#1706=FACE_BOUND('',#1705,.T.);
#1707=ADVANCED_FACE('F323',(#1703,#1706),#1700,.F.);
#1708=CARTESIAN_POINT('',(9.,0.,-15.2));
#1709=DIRECTION('',(0.,0.,-1.));
#1710=DIRECTION('',(-1.,0.,0.));
#1711=AXIS2_PLACEMENT_3D('',#1708,#1709,#1710);
#1712=TOROIDAL_SURFACE('',#1711,5.,1.);
#1713=ORIENTED_EDGE('',*,*,#1520,.F.);
#1714=EDGE_LOOP('',(#1713));
#1715=FACE_BOUND('',#1714,.T.);
#1716=ORIENTED_EDGE('',*,*,#1540,.F.);
#1717=EDGE_LOOP('',(#1716));
#1718=FACE_BOUND('',#1717,.T.);
#1719=ADVANCED_FACE('F321',(#1715,#1718),#1712,.F.);
#1720=CARTESIAN_POINT('',(34.,0.,-15.2));
#1721=DIRECTION('',(0.,0.,-1.));
#1722=DIRECTION('',(-1.,0.,0.));
#1723=AXIS2_PLACEMENT_3D('',#1720,#1721,#1722);
#1724=TOROIDAL_SURFACE('',#1723,5.,1.);
#1725=ORIENTED_EDGE('',*,*,#1472,.F.);
#1726=EDGE_LOOP('',(#1725));
#1727=FACE_BOUND('',#1726,.T.);
#1728=ORIENTED_EDGE('',*,*,#1492,.F.);
#1729=EDGE_LOOP('',(#1728));
#1730=FACE_BOUND('',#1729,.T.);
#1731=ADVANCED_FACE('F50',(#1727,#1730),#1724,.F.);
#1732=CLOSED_SHELL('',(#154,#288,#422,#558,#770,#810,#849,#911,#959,#990,#1146,#1195,#1225,
#1241,#1253,#1297,#1315,#1333,#1350,#1368,#1386,#1403,#1447,#1459,#1479,#1507,#1527,#1555,#1567,
#1579,#1599,#1611,#1631,#1643,#1663,#1675,#1695,#1707,#1719,#1731));
#1733=MANIFOLD_SOLID_BREP('B2',#1732);
#1734=ADVANCED_BREP_SHAPE_REPRESENTATION('',(#18,#1733),#14);
#1735=SHAPE_DEFINITION_REPRESENTATION(#9,#1734);
ENDSEC;
END-ISO-10303-21;
